VERSION 5.8 ;
BUSBITCHARS "[]" ;
DIVIDERCHAR "/" ;
UNITS
    DATABASE MICRONS 1000 ;
END UNITS

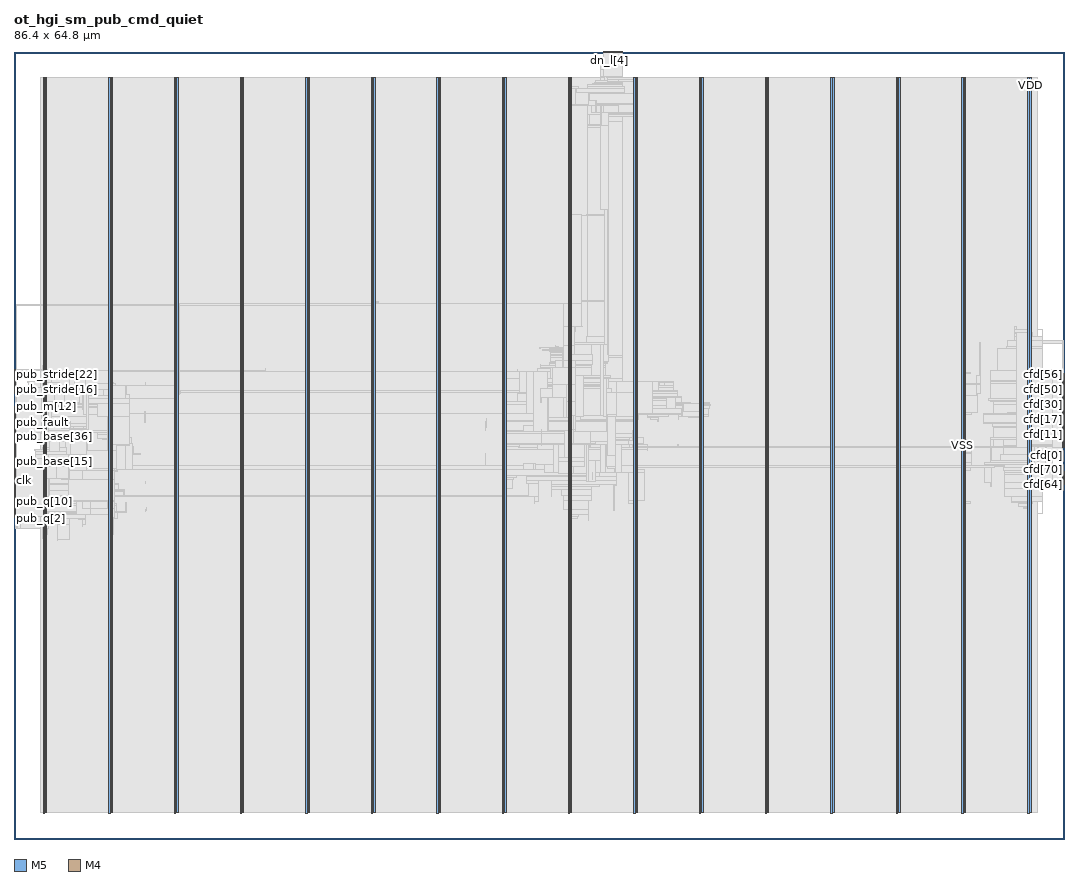
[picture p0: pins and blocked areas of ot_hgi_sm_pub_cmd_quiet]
MACRO ot_hgi_sm_pub_cmd_quiet
  FOREIGN ot_hgi_sm_pub_cmd_quiet 0 0 ;
  CLASS BLOCK ;
  SIZE 86.4 BY 64.8 ;
  PIN agg_r
    DIRECTION INPUT ;
    USE SIGNAL ;
    PORT
      LAYER M5 ;
        RECT  48.528 64.716 48.552 64.8 ;
    END
  END agg_r
  PIN cfd[0]
    DIRECTION OUTPUT ;
    USE SIGNAL ;
    PORT
      LAYER M4 ;
        RECT  86.316 32.208 86.4 32.232 ;
    END
  END cfd[0]
  PIN cfd[10]
    DIRECTION OUTPUT ;
    USE SIGNAL ;
    PORT
      LAYER M4 ;
        RECT  86.316 33.168 86.4 33.192 ;
    END
  END cfd[10]
  PIN cfd[11]
    DIRECTION OUTPUT ;
    USE SIGNAL ;
    PORT
      LAYER M4 ;
        RECT  86.316 33.264 86.4 33.288 ;
    END
  END cfd[11]
  PIN cfd[12]
    DIRECTION OUTPUT ;
    USE SIGNAL ;
    PORT
      LAYER M4 ;
        RECT  86.316 33.36 86.4 33.384 ;
    END
  END cfd[12]
  PIN cfd[13]
    DIRECTION OUTPUT ;
    USE SIGNAL ;
    PORT
      LAYER M4 ;
        RECT  86.316 33.456 86.4 33.48 ;
    END
  END cfd[13]
  PIN cfd[14]
    DIRECTION OUTPUT ;
    USE SIGNAL ;
    PORT
      LAYER M4 ;
        RECT  86.316 33.552 86.4 33.576 ;
    END
  END cfd[14]
  PIN cfd[15]
    DIRECTION OUTPUT ;
    USE SIGNAL ;
    PORT
      LAYER M4 ;
        RECT  86.316 33.648 86.4 33.672 ;
    END
  END cfd[15]
  PIN cfd[16]
    DIRECTION OUTPUT ;
    USE SIGNAL ;
    PORT
      LAYER M4 ;
        RECT  86.316 33.744 86.4 33.768 ;
    END
  END cfd[16]
  PIN cfd[17]
    DIRECTION OUTPUT ;
    USE SIGNAL ;
    PORT
      LAYER M4 ;
        RECT  86.316 33.84 86.4 33.864 ;
    END
  END cfd[17]
  PIN cfd[18]
    DIRECTION OUTPUT ;
    USE SIGNAL ;
    PORT
      LAYER M4 ;
        RECT  86.316 33.936 86.4 33.96 ;
    END
  END cfd[18]
  PIN cfd[19]
    DIRECTION OUTPUT ;
    USE SIGNAL ;
    PORT
      LAYER M4 ;
        RECT  86.316 34.032 86.4 34.056 ;
    END
  END cfd[19]
  PIN cfd[1]
    DIRECTION OUTPUT ;
    USE SIGNAL ;
    PORT
      LAYER M4 ;
        RECT  86.316 32.304 86.4 32.328 ;
    END
  END cfd[1]
  PIN cfd[20]
    DIRECTION OUTPUT ;
    USE SIGNAL ;
    PORT
      LAYER M4 ;
        RECT  86.316 34.128 86.4 34.152 ;
    END
  END cfd[20]
  PIN cfd[21]
    DIRECTION OUTPUT ;
    USE SIGNAL ;
    PORT
      LAYER M4 ;
        RECT  86.316 34.224 86.4 34.248 ;
    END
  END cfd[21]
  PIN cfd[22]
    DIRECTION OUTPUT ;
    USE SIGNAL ;
    PORT
      LAYER M4 ;
        RECT  86.316 34.32 86.4 34.344 ;
    END
  END cfd[22]
  PIN cfd[23]
    DIRECTION OUTPUT ;
    USE SIGNAL ;
    PORT
      LAYER M4 ;
        RECT  86.316 34.416 86.4 34.44 ;
    END
  END cfd[23]
  PIN cfd[24]
    DIRECTION OUTPUT ;
    USE SIGNAL ;
    PORT
      LAYER M4 ;
        RECT  86.316 34.512 86.4 34.536 ;
    END
  END cfd[24]
  PIN cfd[25]
    DIRECTION OUTPUT ;
    USE SIGNAL ;
    PORT
      LAYER M4 ;
        RECT  86.316 34.608 86.4 34.632 ;
    END
  END cfd[25]
  PIN cfd[26]
    DIRECTION OUTPUT ;
    USE SIGNAL ;
    PORT
      LAYER M4 ;
        RECT  86.316 34.704 86.4 34.728 ;
    END
  END cfd[26]
  PIN cfd[27]
    DIRECTION OUTPUT ;
    USE SIGNAL ;
    PORT
      LAYER M4 ;
        RECT  86.316 34.8 86.4 34.824 ;
    END
  END cfd[27]
  PIN cfd[28]
    DIRECTION OUTPUT ;
    USE SIGNAL ;
    PORT
      LAYER M4 ;
        RECT  86.316 34.896 86.4 34.92 ;
    END
  END cfd[28]
  PIN cfd[29]
    DIRECTION OUTPUT ;
    USE SIGNAL ;
    PORT
      LAYER M4 ;
        RECT  86.316 34.992 86.4 35.016 ;
    END
  END cfd[29]
  PIN cfd[2]
    DIRECTION OUTPUT ;
    USE SIGNAL ;
    PORT
      LAYER M4 ;
        RECT  86.316 32.4 86.4 32.424 ;
    END
  END cfd[2]
  PIN cfd[30]
    DIRECTION OUTPUT ;
    USE SIGNAL ;
    PORT
      LAYER M4 ;
        RECT  86.316 35.088 86.4 35.112 ;
    END
  END cfd[30]
  PIN cfd[31]
    DIRECTION OUTPUT ;
    USE SIGNAL ;
    PORT
      LAYER M4 ;
        RECT  86.316 35.184 86.4 35.208 ;
    END
  END cfd[31]
  PIN cfd[32]
    DIRECTION OUTPUT ;
    USE SIGNAL ;
    PORT
      LAYER M4 ;
        RECT  86.316 35.28 86.4 35.304 ;
    END
  END cfd[32]
  PIN cfd[33]
    DIRECTION OUTPUT ;
    USE SIGNAL ;
    PORT
      LAYER M4 ;
        RECT  86.316 35.376 86.4 35.4 ;
    END
  END cfd[33]
  PIN cfd[34]
    DIRECTION OUTPUT ;
    USE SIGNAL ;
    PORT
      LAYER M4 ;
        RECT  86.316 35.472 86.4 35.496 ;
    END
  END cfd[34]
  PIN cfd[35]
    DIRECTION OUTPUT ;
    USE SIGNAL ;
    PORT
      LAYER M4 ;
        RECT  86.316 35.568 86.4 35.592 ;
    END
  END cfd[35]
  PIN cfd[36]
    DIRECTION OUTPUT ;
    USE SIGNAL ;
    PORT
      LAYER M4 ;
        RECT  86.316 35.664 86.4 35.688 ;
    END
  END cfd[36]
  PIN cfd[37]
    DIRECTION OUTPUT ;
    USE SIGNAL ;
    PORT
      LAYER M4 ;
        RECT  86.316 35.76 86.4 35.784 ;
    END
  END cfd[37]
  PIN cfd[38]
    DIRECTION OUTPUT ;
    USE SIGNAL ;
    PORT
      LAYER M4 ;
        RECT  86.316 35.856 86.4 35.88 ;
    END
  END cfd[38]
  PIN cfd[39]
    DIRECTION OUTPUT ;
    USE SIGNAL ;
    PORT
      LAYER M4 ;
        RECT  86.316 35.952 86.4 35.976 ;
    END
  END cfd[39]
  PIN cfd[3]
    DIRECTION OUTPUT ;
    USE SIGNAL ;
    PORT
      LAYER M4 ;
        RECT  86.316 32.496 86.4 32.52 ;
    END
  END cfd[3]
  PIN cfd[40]
    DIRECTION OUTPUT ;
    USE SIGNAL ;
    PORT
      LAYER M4 ;
        RECT  86.316 36.048 86.4 36.072 ;
    END
  END cfd[40]
  PIN cfd[41]
    DIRECTION OUTPUT ;
    USE SIGNAL ;
    PORT
      LAYER M4 ;
        RECT  86.316 36.144 86.4 36.168 ;
    END
  END cfd[41]
  PIN cfd[42]
    DIRECTION OUTPUT ;
    USE SIGNAL ;
    PORT
      LAYER M4 ;
        RECT  86.316 36.24 86.4 36.264 ;
    END
  END cfd[42]
  PIN cfd[43]
    DIRECTION OUTPUT ;
    USE SIGNAL ;
    PORT
      LAYER M4 ;
        RECT  86.316 36.336 86.4 36.36 ;
    END
  END cfd[43]
  PIN cfd[44]
    DIRECTION OUTPUT ;
    USE SIGNAL ;
    PORT
      LAYER M4 ;
        RECT  86.316 36.432 86.4 36.456 ;
    END
  END cfd[44]
  PIN cfd[45]
    DIRECTION OUTPUT ;
    USE SIGNAL ;
    PORT
      LAYER M4 ;
        RECT  86.316 36.528 86.4 36.552 ;
    END
  END cfd[45]
  PIN cfd[46]
    DIRECTION OUTPUT ;
    USE SIGNAL ;
    PORT
      LAYER M4 ;
        RECT  86.316 36.624 86.4 36.648 ;
    END
  END cfd[46]
  PIN cfd[47]
    DIRECTION OUTPUT ;
    USE SIGNAL ;
    PORT
      LAYER M4 ;
        RECT  86.316 36.72 86.4 36.744 ;
    END
  END cfd[47]
  PIN cfd[48]
    DIRECTION OUTPUT ;
    USE SIGNAL ;
    PORT
      LAYER M4 ;
        RECT  86.316 36.816 86.4 36.84 ;
    END
  END cfd[48]
  PIN cfd[49]
    DIRECTION OUTPUT ;
    USE SIGNAL ;
    PORT
      LAYER M4 ;
        RECT  86.316 36.912 86.4 36.936 ;
    END
  END cfd[49]
  PIN cfd[4]
    DIRECTION OUTPUT ;
    USE SIGNAL ;
    PORT
      LAYER M4 ;
        RECT  86.316 32.592 86.4 32.616 ;
    END
  END cfd[4]
  PIN cfd[50]
    DIRECTION OUTPUT ;
    USE SIGNAL ;
    PORT
      LAYER M4 ;
        RECT  86.316 37.008 86.4 37.032 ;
    END
  END cfd[50]
  PIN cfd[51]
    DIRECTION OUTPUT ;
    USE SIGNAL ;
    PORT
      LAYER M4 ;
        RECT  86.316 37.104 86.4 37.128 ;
    END
  END cfd[51]
  PIN cfd[52]
    DIRECTION OUTPUT ;
    USE SIGNAL ;
    PORT
      LAYER M4 ;
        RECT  86.316 37.2 86.4 37.224 ;
    END
  END cfd[52]
  PIN cfd[53]
    DIRECTION OUTPUT ;
    USE SIGNAL ;
    PORT
      LAYER M4 ;
        RECT  86.316 37.296 86.4 37.32 ;
    END
  END cfd[53]
  PIN cfd[54]
    DIRECTION OUTPUT ;
    USE SIGNAL ;
    PORT
      LAYER M4 ;
        RECT  86.316 37.392 86.4 37.416 ;
    END
  END cfd[54]
  PIN cfd[55]
    DIRECTION OUTPUT ;
    USE SIGNAL ;
    PORT
      LAYER M4 ;
        RECT  86.316 37.488 86.4 37.512 ;
    END
  END cfd[55]
  PIN cfd[56]
    DIRECTION OUTPUT ;
    USE SIGNAL ;
    PORT
      LAYER M4 ;
        RECT  86.316 37.584 86.4 37.608 ;
    END
  END cfd[56]
  PIN cfd[57]
    DIRECTION OUTPUT ;
    USE SIGNAL ;
    PORT
      LAYER M4 ;
        RECT  86.316 37.68 86.4 37.704 ;
    END
  END cfd[57]
  PIN cfd[58]
    DIRECTION OUTPUT ;
    USE SIGNAL ;
    PORT
      LAYER M4 ;
        RECT  86.316 37.776 86.4 37.8 ;
    END
  END cfd[58]
  PIN cfd[59]
    DIRECTION OUTPUT ;
    USE SIGNAL ;
    PORT
      LAYER M4 ;
        RECT  86.316 37.872 86.4 37.896 ;
    END
  END cfd[59]
  PIN cfd[5]
    DIRECTION OUTPUT ;
    USE SIGNAL ;
    PORT
      LAYER M4 ;
        RECT  86.316 32.688 86.4 32.712 ;
    END
  END cfd[5]
  PIN cfd[60]
    DIRECTION OUTPUT ;
    USE SIGNAL ;
    PORT
      LAYER M4 ;
        RECT  86.316 37.968 86.4 37.992 ;
    END
  END cfd[60]
  PIN cfd[61]
    DIRECTION OUTPUT ;
    USE SIGNAL ;
    PORT
      LAYER M4 ;
        RECT  86.316 38.064 86.4 38.088 ;
    END
  END cfd[61]
  PIN cfd[62]
    DIRECTION OUTPUT ;
    USE SIGNAL ;
    PORT
      LAYER M4 ;
        RECT  86.316 38.16 86.4 38.184 ;
    END
  END cfd[62]
  PIN cfd[63]
    DIRECTION OUTPUT ;
    USE SIGNAL ;
    PORT
      LAYER M4 ;
        RECT  86.316 38.256 86.4 38.28 ;
    END
  END cfd[63]
  PIN cfd[64]
    DIRECTION OUTPUT ;
    USE SIGNAL ;
    PORT
      LAYER M4 ;
        RECT  86.316 29.136 86.4 29.16 ;
    END
  END cfd[64]
  PIN cfd[65]
    DIRECTION OUTPUT ;
    USE SIGNAL ;
    PORT
      LAYER M4 ;
        RECT  86.316 29.232 86.4 29.256 ;
    END
  END cfd[65]
  PIN cfd[66]
    DIRECTION OUTPUT ;
    USE SIGNAL ;
    PORT
      LAYER M4 ;
        RECT  86.316 29.328 86.4 29.352 ;
    END
  END cfd[66]
  PIN cfd[67]
    DIRECTION OUTPUT ;
    USE SIGNAL ;
    PORT
      LAYER M4 ;
        RECT  86.316 29.424 86.4 29.448 ;
    END
  END cfd[67]
  PIN cfd[68]
    DIRECTION OUTPUT ;
    USE SIGNAL ;
    PORT
      LAYER M4 ;
        RECT  86.316 29.52 86.4 29.544 ;
    END
  END cfd[68]
  PIN cfd[69]
    DIRECTION OUTPUT ;
    USE SIGNAL ;
    PORT
      LAYER M4 ;
        RECT  86.316 29.616 86.4 29.64 ;
    END
  END cfd[69]
  PIN cfd[6]
    DIRECTION OUTPUT ;
    USE SIGNAL ;
    PORT
      LAYER M4 ;
        RECT  86.316 32.784 86.4 32.808 ;
    END
  END cfd[6]
  PIN cfd[70]
    DIRECTION OUTPUT ;
    USE SIGNAL ;
    PORT
      LAYER M4 ;
        RECT  86.316 29.712 86.4 29.736 ;
    END
  END cfd[70]
  PIN cfd[71]
    DIRECTION OUTPUT ;
    USE SIGNAL ;
    PORT
      LAYER M4 ;
        RECT  86.316 29.808 86.4 29.832 ;
    END
  END cfd[71]
  PIN cfd[72]
    DIRECTION OUTPUT ;
    USE SIGNAL ;
    PORT
      LAYER M4 ;
        RECT  86.316 29.904 86.4 29.928 ;
    END
  END cfd[72]
  PIN cfd[73]
    DIRECTION OUTPUT ;
    USE SIGNAL ;
    PORT
      LAYER M4 ;
        RECT  86.316 30 86.4 30.024 ;
    END
  END cfd[73]
  PIN cfd[74]
    DIRECTION OUTPUT ;
    USE SIGNAL ;
    PORT
      LAYER M4 ;
        RECT  86.316 30.096 86.4 30.12 ;
    END
  END cfd[74]
  PIN cfd[7]
    DIRECTION OUTPUT ;
    USE SIGNAL ;
    PORT
      LAYER M4 ;
        RECT  86.316 32.88 86.4 32.904 ;
    END
  END cfd[7]
  PIN cfd[8]
    DIRECTION OUTPUT ;
    USE SIGNAL ;
    PORT
      LAYER M4 ;
        RECT  86.316 32.976 86.4 33 ;
    END
  END cfd[8]
  PIN cfd[9]
    DIRECTION OUTPUT ;
    USE SIGNAL ;
    PORT
      LAYER M4 ;
        RECT  86.316 33.072 86.4 33.096 ;
    END
  END cfd[9]
  PIN cgo
    DIRECTION OUTPUT ;
    USE SIGNAL ;
    PORT
      LAYER M4 ;
        RECT  86.316 30.192 86.4 30.216 ;
    END
  END cgo
  PIN clk
    DIRECTION INPUT ;
    USE SIGNAL ;
    PORT
      LAYER M4 ;
        RECT  0 29.52 0.084 29.544 ;
    END
  END clk
  PIN dn_l[0]
    DIRECTION INPUT ;
    USE SIGNAL ;
    PORT
      LAYER M5 ;
        RECT  48.624 64.716 48.648 64.8 ;
    END
  END dn_l[0]
  PIN dn_l[1]
    DIRECTION INPUT ;
    USE SIGNAL ;
    PORT
      LAYER M5 ;
        RECT  48.72 64.716 48.744 64.8 ;
    END
  END dn_l[1]
  PIN dn_l[2]
    DIRECTION INPUT ;
    USE SIGNAL ;
    PORT
      LAYER M5 ;
        RECT  48.816 64.716 48.84 64.8 ;
    END
  END dn_l[2]
  PIN dn_l[3]
    DIRECTION INPUT ;
    USE SIGNAL ;
    PORT
      LAYER M5 ;
        RECT  48.912 64.716 48.936 64.8 ;
    END
  END dn_l[3]
  PIN dn_l[4]
    DIRECTION INPUT ;
    USE SIGNAL ;
    PORT
      LAYER M5 ;
        RECT  49.008 64.716 49.032 64.8 ;
    END
  END dn_l[4]
  PIN dn_l[5]
    DIRECTION INPUT ;
    USE SIGNAL ;
    PORT
      LAYER M5 ;
        RECT  49.104 64.716 49.128 64.8 ;
    END
  END dn_l[5]
  PIN dn_l[6]
    DIRECTION INPUT ;
    USE SIGNAL ;
    PORT
      LAYER M5 ;
        RECT  49.2 64.716 49.224 64.8 ;
    END
  END dn_l[6]
  PIN dn_l[7]
    DIRECTION INPUT ;
    USE SIGNAL ;
    PORT
      LAYER M5 ;
        RECT  49.296 64.716 49.32 64.8 ;
    END
  END dn_l[7]
  PIN ft_l[0]
    DIRECTION INPUT ;
    USE SIGNAL ;
    PORT
      LAYER M5 ;
        RECT  49.392 64.716 49.416 64.8 ;
    END
  END ft_l[0]
  PIN ft_l[1]
    DIRECTION INPUT ;
    USE SIGNAL ;
    PORT
      LAYER M5 ;
        RECT  49.488 64.716 49.512 64.8 ;
    END
  END ft_l[1]
  PIN ft_l[2]
    DIRECTION INPUT ;
    USE SIGNAL ;
    PORT
      LAYER M5 ;
        RECT  49.584 64.716 49.608 64.8 ;
    END
  END ft_l[2]
  PIN ft_l[3]
    DIRECTION INPUT ;
    USE SIGNAL ;
    PORT
      LAYER M5 ;
        RECT  49.68 64.716 49.704 64.8 ;
    END
  END ft_l[3]
  PIN ft_l[4]
    DIRECTION INPUT ;
    USE SIGNAL ;
    PORT
      LAYER M5 ;
        RECT  49.776 64.716 49.8 64.8 ;
    END
  END ft_l[4]
  PIN ft_l[5]
    DIRECTION INPUT ;
    USE SIGNAL ;
    PORT
      LAYER M5 ;
        RECT  49.872 64.716 49.896 64.8 ;
    END
  END ft_l[5]
  PIN ft_l[6]
    DIRECTION INPUT ;
    USE SIGNAL ;
    PORT
      LAYER M5 ;
        RECT  49.968 64.716 49.992 64.8 ;
    END
  END ft_l[6]
  PIN ft_l[7]
    DIRECTION INPUT ;
    USE SIGNAL ;
    PORT
      LAYER M5 ;
        RECT  50.064 64.716 50.088 64.8 ;
    END
  END ft_l[7]
  PIN pub_base[0]
    DIRECTION INPUT ;
    USE SIGNAL ;
    PORT
      LAYER M4 ;
        RECT  0 29.616 0.084 29.64 ;
    END
  END pub_base[0]
  PIN pub_base[10]
    DIRECTION INPUT ;
    USE SIGNAL ;
    PORT
      LAYER M4 ;
        RECT  0 30.576 0.084 30.6 ;
    END
  END pub_base[10]
  PIN pub_base[11]
    DIRECTION INPUT ;
    USE SIGNAL ;
    PORT
      LAYER M4 ;
        RECT  0 30.672 0.084 30.696 ;
    END
  END pub_base[11]
  PIN pub_base[12]
    DIRECTION INPUT ;
    USE SIGNAL ;
    PORT
      LAYER M4 ;
        RECT  0 30.768 0.084 30.792 ;
    END
  END pub_base[12]
  PIN pub_base[13]
    DIRECTION INPUT ;
    USE SIGNAL ;
    PORT
      LAYER M4 ;
        RECT  0 30.864 0.084 30.888 ;
    END
  END pub_base[13]
  PIN pub_base[14]
    DIRECTION INPUT ;
    USE SIGNAL ;
    PORT
      LAYER M4 ;
        RECT  0 30.96 0.084 30.984 ;
    END
  END pub_base[14]
  PIN pub_base[15]
    DIRECTION INPUT ;
    USE SIGNAL ;
    PORT
      LAYER M4 ;
        RECT  0 31.056 0.084 31.08 ;
    END
  END pub_base[15]
  PIN pub_base[16]
    DIRECTION INPUT ;
    USE SIGNAL ;
    PORT
      LAYER M4 ;
        RECT  0 31.152 0.084 31.176 ;
    END
  END pub_base[16]
  PIN pub_base[17]
    DIRECTION INPUT ;
    USE SIGNAL ;
    PORT
      LAYER M4 ;
        RECT  0 31.248 0.084 31.272 ;
    END
  END pub_base[17]
  PIN pub_base[18]
    DIRECTION INPUT ;
    USE SIGNAL ;
    PORT
      LAYER M4 ;
        RECT  0 31.344 0.084 31.368 ;
    END
  END pub_base[18]
  PIN pub_base[19]
    DIRECTION INPUT ;
    USE SIGNAL ;
    PORT
      LAYER M4 ;
        RECT  0 31.44 0.084 31.464 ;
    END
  END pub_base[19]
  PIN pub_base[1]
    DIRECTION INPUT ;
    USE SIGNAL ;
    PORT
      LAYER M4 ;
        RECT  0 29.712 0.084 29.736 ;
    END
  END pub_base[1]
  PIN pub_base[20]
    DIRECTION INPUT ;
    USE SIGNAL ;
    PORT
      LAYER M4 ;
        RECT  0 31.536 0.084 31.56 ;
    END
  END pub_base[20]
  PIN pub_base[21]
    DIRECTION INPUT ;
    USE SIGNAL ;
    PORT
      LAYER M4 ;
        RECT  0 31.632 0.084 31.656 ;
    END
  END pub_base[21]
  PIN pub_base[22]
    DIRECTION INPUT ;
    USE SIGNAL ;
    PORT
      LAYER M4 ;
        RECT  0 31.728 0.084 31.752 ;
    END
  END pub_base[22]
  PIN pub_base[23]
    DIRECTION INPUT ;
    USE SIGNAL ;
    PORT
      LAYER M4 ;
        RECT  0 31.824 0.084 31.848 ;
    END
  END pub_base[23]
  PIN pub_base[24]
    DIRECTION INPUT ;
    USE SIGNAL ;
    PORT
      LAYER M4 ;
        RECT  0 31.92 0.084 31.944 ;
    END
  END pub_base[24]
  PIN pub_base[25]
    DIRECTION INPUT ;
    USE SIGNAL ;
    PORT
      LAYER M4 ;
        RECT  0 32.016 0.084 32.04 ;
    END
  END pub_base[25]
  PIN pub_base[26]
    DIRECTION INPUT ;
    USE SIGNAL ;
    PORT
      LAYER M4 ;
        RECT  0 32.112 0.084 32.136 ;
    END
  END pub_base[26]
  PIN pub_base[27]
    DIRECTION INPUT ;
    USE SIGNAL ;
    PORT
      LAYER M4 ;
        RECT  0 32.208 0.084 32.232 ;
    END
  END pub_base[27]
  PIN pub_base[28]
    DIRECTION INPUT ;
    USE SIGNAL ;
    PORT
      LAYER M4 ;
        RECT  0 32.304 0.084 32.328 ;
    END
  END pub_base[28]
  PIN pub_base[29]
    DIRECTION INPUT ;
    USE SIGNAL ;
    PORT
      LAYER M4 ;
        RECT  0 32.4 0.084 32.424 ;
    END
  END pub_base[29]
  PIN pub_base[2]
    DIRECTION INPUT ;
    USE SIGNAL ;
    PORT
      LAYER M4 ;
        RECT  0 29.808 0.084 29.832 ;
    END
  END pub_base[2]
  PIN pub_base[30]
    DIRECTION INPUT ;
    USE SIGNAL ;
    PORT
      LAYER M4 ;
        RECT  0 32.496 0.084 32.52 ;
    END
  END pub_base[30]
  PIN pub_base[31]
    DIRECTION INPUT ;
    USE SIGNAL ;
    PORT
      LAYER M4 ;
        RECT  0 32.592 0.084 32.616 ;
    END
  END pub_base[31]
  PIN pub_base[32]
    DIRECTION INPUT ;
    USE SIGNAL ;
    PORT
      LAYER M4 ;
        RECT  0 32.688 0.084 32.712 ;
    END
  END pub_base[32]
  PIN pub_base[33]
    DIRECTION INPUT ;
    USE SIGNAL ;
    PORT
      LAYER M4 ;
        RECT  0 32.784 0.084 32.808 ;
    END
  END pub_base[33]
  PIN pub_base[34]
    DIRECTION INPUT ;
    USE SIGNAL ;
    PORT
      LAYER M4 ;
        RECT  0 32.88 0.084 32.904 ;
    END
  END pub_base[34]
  PIN pub_base[35]
    DIRECTION INPUT ;
    USE SIGNAL ;
    PORT
      LAYER M4 ;
        RECT  0 32.976 0.084 33 ;
    END
  END pub_base[35]
  PIN pub_base[36]
    DIRECTION INPUT ;
    USE SIGNAL ;
    PORT
      LAYER M4 ;
        RECT  0 33.072 0.084 33.096 ;
    END
  END pub_base[36]
  PIN pub_base[37]
    DIRECTION INPUT ;
    USE SIGNAL ;
    PORT
      LAYER M4 ;
        RECT  0 33.168 0.084 33.192 ;
    END
  END pub_base[37]
  PIN pub_base[38]
    DIRECTION INPUT ;
    USE SIGNAL ;
    PORT
      LAYER M4 ;
        RECT  0 33.264 0.084 33.288 ;
    END
  END pub_base[38]
  PIN pub_base[39]
    DIRECTION INPUT ;
    USE SIGNAL ;
    PORT
      LAYER M4 ;
        RECT  0 33.36 0.084 33.384 ;
    END
  END pub_base[39]
  PIN pub_base[3]
    DIRECTION INPUT ;
    USE SIGNAL ;
    PORT
      LAYER M4 ;
        RECT  0 29.904 0.084 29.928 ;
    END
  END pub_base[3]
  PIN pub_base[4]
    DIRECTION INPUT ;
    USE SIGNAL ;
    PORT
      LAYER M4 ;
        RECT  0 30 0.084 30.024 ;
    END
  END pub_base[4]
  PIN pub_base[5]
    DIRECTION INPUT ;
    USE SIGNAL ;
    PORT
      LAYER M4 ;
        RECT  0 30.096 0.084 30.12 ;
    END
  END pub_base[5]
  PIN pub_base[6]
    DIRECTION INPUT ;
    USE SIGNAL ;
    PORT
      LAYER M4 ;
        RECT  0 30.192 0.084 30.216 ;
    END
  END pub_base[6]
  PIN pub_base[7]
    DIRECTION INPUT ;
    USE SIGNAL ;
    PORT
      LAYER M4 ;
        RECT  0 30.288 0.084 30.312 ;
    END
  END pub_base[7]
  PIN pub_base[8]
    DIRECTION INPUT ;
    USE SIGNAL ;
    PORT
      LAYER M4 ;
        RECT  0 30.384 0.084 30.408 ;
    END
  END pub_base[8]
  PIN pub_base[9]
    DIRECTION INPUT ;
    USE SIGNAL ;
    PORT
      LAYER M4 ;
        RECT  0 30.48 0.084 30.504 ;
    END
  END pub_base[9]
  PIN pub_bf16
    DIRECTION INPUT ;
    USE SIGNAL ;
    PORT
      LAYER M4 ;
        RECT  0 33.456 0.084 33.48 ;
    END
  END pub_bf16
  PIN pub_done
    DIRECTION OUTPUT ;
    USE SIGNAL ;
    PORT
      LAYER M4 ;
        RECT  0 33.552 0.084 33.576 ;
    END
  END pub_done
  PIN pub_fault
    DIRECTION OUTPUT ;
    USE SIGNAL ;
    PORT
      LAYER M4 ;
        RECT  0 33.648 0.084 33.672 ;
    END
  END pub_fault
  PIN pub_m[0]
    DIRECTION INPUT ;
    USE SIGNAL ;
    PORT
      LAYER M4 ;
        RECT  0 33.744 0.084 33.768 ;
    END
  END pub_m[0]
  PIN pub_m[10]
    DIRECTION INPUT ;
    USE SIGNAL ;
    PORT
      LAYER M4 ;
        RECT  0 34.704 0.084 34.728 ;
    END
  END pub_m[10]
  PIN pub_m[11]
    DIRECTION INPUT ;
    USE SIGNAL ;
    PORT
      LAYER M4 ;
        RECT  0 34.8 0.084 34.824 ;
    END
  END pub_m[11]
  PIN pub_m[12]
    DIRECTION INPUT ;
    USE SIGNAL ;
    PORT
      LAYER M4 ;
        RECT  0 34.896 0.084 34.92 ;
    END
  END pub_m[12]
  PIN pub_m[13]
    DIRECTION INPUT ;
    USE SIGNAL ;
    PORT
      LAYER M4 ;
        RECT  0 34.992 0.084 35.016 ;
    END
  END pub_m[13]
  PIN pub_m[14]
    DIRECTION INPUT ;
    USE SIGNAL ;
    PORT
      LAYER M4 ;
        RECT  0 35.088 0.084 35.112 ;
    END
  END pub_m[14]
  PIN pub_m[15]
    DIRECTION INPUT ;
    USE SIGNAL ;
    PORT
      LAYER M4 ;
        RECT  0 35.184 0.084 35.208 ;
    END
  END pub_m[15]
  PIN pub_m[16]
    DIRECTION INPUT ;
    USE SIGNAL ;
    PORT
      LAYER M4 ;
        RECT  0 35.28 0.084 35.304 ;
    END
  END pub_m[16]
  PIN pub_m[17]
    DIRECTION INPUT ;
    USE SIGNAL ;
    PORT
      LAYER M4 ;
        RECT  0 35.376 0.084 35.4 ;
    END
  END pub_m[17]
  PIN pub_m[18]
    DIRECTION INPUT ;
    USE SIGNAL ;
    PORT
      LAYER M4 ;
        RECT  0 35.472 0.084 35.496 ;
    END
  END pub_m[18]
  PIN pub_m[19]
    DIRECTION INPUT ;
    USE SIGNAL ;
    PORT
      LAYER M4 ;
        RECT  0 35.568 0.084 35.592 ;
    END
  END pub_m[19]
  PIN pub_m[1]
    DIRECTION INPUT ;
    USE SIGNAL ;
    PORT
      LAYER M4 ;
        RECT  0 33.84 0.084 33.864 ;
    END
  END pub_m[1]
  PIN pub_m[2]
    DIRECTION INPUT ;
    USE SIGNAL ;
    PORT
      LAYER M4 ;
        RECT  0 33.936 0.084 33.96 ;
    END
  END pub_m[2]
  PIN pub_m[3]
    DIRECTION INPUT ;
    USE SIGNAL ;
    PORT
      LAYER M4 ;
        RECT  0 34.032 0.084 34.056 ;
    END
  END pub_m[3]
  PIN pub_m[4]
    DIRECTION INPUT ;
    USE SIGNAL ;
    PORT
      LAYER M4 ;
        RECT  0 34.128 0.084 34.152 ;
    END
  END pub_m[4]
  PIN pub_m[5]
    DIRECTION INPUT ;
    USE SIGNAL ;
    PORT
      LAYER M4 ;
        RECT  0 34.224 0.084 34.248 ;
    END
  END pub_m[5]
  PIN pub_m[6]
    DIRECTION INPUT ;
    USE SIGNAL ;
    PORT
      LAYER M4 ;
        RECT  0 34.32 0.084 34.344 ;
    END
  END pub_m[6]
  PIN pub_m[7]
    DIRECTION INPUT ;
    USE SIGNAL ;
    PORT
      LAYER M4 ;
        RECT  0 34.416 0.084 34.44 ;
    END
  END pub_m[7]
  PIN pub_m[8]
    DIRECTION INPUT ;
    USE SIGNAL ;
    PORT
      LAYER M4 ;
        RECT  0 34.512 0.084 34.536 ;
    END
  END pub_m[8]
  PIN pub_m[9]
    DIRECTION INPUT ;
    USE SIGNAL ;
    PORT
      LAYER M4 ;
        RECT  0 34.608 0.084 34.632 ;
    END
  END pub_m[9]
  PIN pub_p[0]
    DIRECTION INPUT ;
    USE SIGNAL ;
    PORT
      LAYER M4 ;
        RECT  0 26.448 0.084 26.472 ;
    END
  END pub_p[0]
  PIN pub_p[1]
    DIRECTION INPUT ;
    USE SIGNAL ;
    PORT
      LAYER M4 ;
        RECT  0 26.544 0.084 26.568 ;
    END
  END pub_p[1]
  PIN pub_p[2]
    DIRECTION INPUT ;
    USE SIGNAL ;
    PORT
      LAYER M4 ;
        RECT  0 26.64 0.084 26.664 ;
    END
  END pub_p[2]
  PIN pub_p[3]
    DIRECTION INPUT ;
    USE SIGNAL ;
    PORT
      LAYER M4 ;
        RECT  0 26.736 0.084 26.76 ;
    END
  END pub_p[3]
  PIN pub_q[0]
    DIRECTION INPUT ;
    USE SIGNAL ;
    PORT
      LAYER M4 ;
        RECT  0 26.832 0.084 26.856 ;
    END
  END pub_q[0]
  PIN pub_q[10]
    DIRECTION INPUT ;
    USE SIGNAL ;
    PORT
      LAYER M4 ;
        RECT  0 27.792 0.084 27.816 ;
    END
  END pub_q[10]
  PIN pub_q[11]
    DIRECTION INPUT ;
    USE SIGNAL ;
    PORT
      LAYER M4 ;
        RECT  0 27.888 0.084 27.912 ;
    END
  END pub_q[11]
  PIN pub_q[12]
    DIRECTION INPUT ;
    USE SIGNAL ;
    PORT
      LAYER M4 ;
        RECT  0 27.984 0.084 28.008 ;
    END
  END pub_q[12]
  PIN pub_q[1]
    DIRECTION INPUT ;
    USE SIGNAL ;
    PORT
      LAYER M4 ;
        RECT  0 26.928 0.084 26.952 ;
    END
  END pub_q[1]
  PIN pub_q[2]
    DIRECTION INPUT ;
    USE SIGNAL ;
    PORT
      LAYER M4 ;
        RECT  0 27.024 0.084 27.048 ;
    END
  END pub_q[2]
  PIN pub_q[3]
    DIRECTION INPUT ;
    USE SIGNAL ;
    PORT
      LAYER M4 ;
        RECT  0 27.12 0.084 27.144 ;
    END
  END pub_q[3]
  PIN pub_q[4]
    DIRECTION INPUT ;
    USE SIGNAL ;
    PORT
      LAYER M4 ;
        RECT  0 27.216 0.084 27.24 ;
    END
  END pub_q[4]
  PIN pub_q[5]
    DIRECTION INPUT ;
    USE SIGNAL ;
    PORT
      LAYER M4 ;
        RECT  0 27.312 0.084 27.336 ;
    END
  END pub_q[5]
  PIN pub_q[6]
    DIRECTION INPUT ;
    USE SIGNAL ;
    PORT
      LAYER M4 ;
        RECT  0 27.408 0.084 27.432 ;
    END
  END pub_q[6]
  PIN pub_q[7]
    DIRECTION INPUT ;
    USE SIGNAL ;
    PORT
      LAYER M4 ;
        RECT  0 27.504 0.084 27.528 ;
    END
  END pub_q[7]
  PIN pub_q[8]
    DIRECTION INPUT ;
    USE SIGNAL ;
    PORT
      LAYER M4 ;
        RECT  0 27.6 0.084 27.624 ;
    END
  END pub_q[8]
  PIN pub_q[9]
    DIRECTION INPUT ;
    USE SIGNAL ;
    PORT
      LAYER M4 ;
        RECT  0 27.696 0.084 27.72 ;
    END
  END pub_q[9]
  PIN pub_rdy
    DIRECTION OUTPUT ;
    USE SIGNAL ;
    PORT
      LAYER M4 ;
        RECT  0 28.08 0.084 28.104 ;
    END
  END pub_rdy
  PIN pub_space[0]
    DIRECTION INPUT ;
    USE SIGNAL ;
    PORT
      LAYER M4 ;
        RECT  0 28.176 0.084 28.2 ;
    END
  END pub_space[0]
  PIN pub_space[1]
    DIRECTION INPUT ;
    USE SIGNAL ;
    PORT
      LAYER M4 ;
        RECT  0 28.272 0.084 28.296 ;
    END
  END pub_space[1]
  PIN pub_stride[0]
    DIRECTION INPUT ;
    USE SIGNAL ;
    PORT
      LAYER M4 ;
        RECT  0 28.368 0.084 28.392 ;
    END
  END pub_stride[0]
  PIN pub_stride[10]
    DIRECTION INPUT ;
    USE SIGNAL ;
    PORT
      LAYER M4 ;
        RECT  0 29.328 0.084 29.352 ;
    END
  END pub_stride[10]
  PIN pub_stride[11]
    DIRECTION INPUT ;
    USE SIGNAL ;
    PORT
      LAYER M4 ;
        RECT  0 29.424 0.084 29.448 ;
    END
  END pub_stride[11]
  PIN pub_stride[12]
    DIRECTION INPUT ;
    USE SIGNAL ;
    PORT
      LAYER M4 ;
        RECT  0 36.624 0.084 36.648 ;
    END
  END pub_stride[12]
  PIN pub_stride[13]
    DIRECTION INPUT ;
    USE SIGNAL ;
    PORT
      LAYER M4 ;
        RECT  0 36.72 0.084 36.744 ;
    END
  END pub_stride[13]
  PIN pub_stride[14]
    DIRECTION INPUT ;
    USE SIGNAL ;
    PORT
      LAYER M4 ;
        RECT  0 36.816 0.084 36.84 ;
    END
  END pub_stride[14]
  PIN pub_stride[15]
    DIRECTION INPUT ;
    USE SIGNAL ;
    PORT
      LAYER M4 ;
        RECT  0 36.912 0.084 36.936 ;
    END
  END pub_stride[15]
  PIN pub_stride[16]
    DIRECTION INPUT ;
    USE SIGNAL ;
    PORT
      LAYER M4 ;
        RECT  0 37.008 0.084 37.032 ;
    END
  END pub_stride[16]
  PIN pub_stride[17]
    DIRECTION INPUT ;
    USE SIGNAL ;
    PORT
      LAYER M4 ;
        RECT  0 37.104 0.084 37.128 ;
    END
  END pub_stride[17]
  PIN pub_stride[18]
    DIRECTION INPUT ;
    USE SIGNAL ;
    PORT
      LAYER M4 ;
        RECT  0 37.2 0.084 37.224 ;
    END
  END pub_stride[18]
  PIN pub_stride[19]
    DIRECTION INPUT ;
    USE SIGNAL ;
    PORT
      LAYER M4 ;
        RECT  0 37.296 0.084 37.32 ;
    END
  END pub_stride[19]
  PIN pub_stride[1]
    DIRECTION INPUT ;
    USE SIGNAL ;
    PORT
      LAYER M4 ;
        RECT  0 28.464 0.084 28.488 ;
    END
  END pub_stride[1]
  PIN pub_stride[20]
    DIRECTION INPUT ;
    USE SIGNAL ;
    PORT
      LAYER M4 ;
        RECT  0 37.392 0.084 37.416 ;
    END
  END pub_stride[20]
  PIN pub_stride[21]
    DIRECTION INPUT ;
    USE SIGNAL ;
    PORT
      LAYER M4 ;
        RECT  0 37.488 0.084 37.512 ;
    END
  END pub_stride[21]
  PIN pub_stride[22]
    DIRECTION INPUT ;
    USE SIGNAL ;
    PORT
      LAYER M4 ;
        RECT  0 37.584 0.084 37.608 ;
    END
  END pub_stride[22]
  PIN pub_stride[23]
    DIRECTION INPUT ;
    USE SIGNAL ;
    PORT
      LAYER M4 ;
        RECT  0 37.68 0.084 37.704 ;
    END
  END pub_stride[23]
  PIN pub_stride[24]
    DIRECTION INPUT ;
    USE SIGNAL ;
    PORT
      LAYER M4 ;
        RECT  0 37.776 0.084 37.8 ;
    END
  END pub_stride[24]
  PIN pub_stride[25]
    DIRECTION INPUT ;
    USE SIGNAL ;
    PORT
      LAYER M4 ;
        RECT  0 37.872 0.084 37.896 ;
    END
  END pub_stride[25]
  PIN pub_stride[26]
    DIRECTION INPUT ;
    USE SIGNAL ;
    PORT
      LAYER M4 ;
        RECT  0 37.968 0.084 37.992 ;
    END
  END pub_stride[26]
  PIN pub_stride[27]
    DIRECTION INPUT ;
    USE SIGNAL ;
    PORT
      LAYER M4 ;
        RECT  0 38.064 0.084 38.088 ;
    END
  END pub_stride[27]
  PIN pub_stride[28]
    DIRECTION INPUT ;
    USE SIGNAL ;
    PORT
      LAYER M4 ;
        RECT  0 38.16 0.084 38.184 ;
    END
  END pub_stride[28]
  PIN pub_stride[29]
    DIRECTION INPUT ;
    USE SIGNAL ;
    PORT
      LAYER M4 ;
        RECT  0 38.256 0.084 38.28 ;
    END
  END pub_stride[29]
  PIN pub_stride[2]
    DIRECTION INPUT ;
    USE SIGNAL ;
    PORT
      LAYER M4 ;
        RECT  0 28.56 0.084 28.584 ;
    END
  END pub_stride[2]
  PIN pub_stride[30]
    DIRECTION INPUT ;
    USE SIGNAL ;
    PORT
      LAYER M4 ;
        RECT  0 38.352 0.084 38.376 ;
    END
  END pub_stride[30]
  PIN pub_stride[31]
    DIRECTION INPUT ;
    USE SIGNAL ;
    PORT
      LAYER M4 ;
        RECT  0 38.448 0.084 38.472 ;
    END
  END pub_stride[31]
  PIN pub_stride[3]
    DIRECTION INPUT ;
    USE SIGNAL ;
    PORT
      LAYER M4 ;
        RECT  0 28.656 0.084 28.68 ;
    END
  END pub_stride[3]
  PIN pub_stride[4]
    DIRECTION INPUT ;
    USE SIGNAL ;
    PORT
      LAYER M4 ;
        RECT  0 28.752 0.084 28.776 ;
    END
  END pub_stride[4]
  PIN pub_stride[5]
    DIRECTION INPUT ;
    USE SIGNAL ;
    PORT
      LAYER M4 ;
        RECT  0 28.848 0.084 28.872 ;
    END
  END pub_stride[5]
  PIN pub_stride[6]
    DIRECTION INPUT ;
    USE SIGNAL ;
    PORT
      LAYER M4 ;
        RECT  0 28.944 0.084 28.968 ;
    END
  END pub_stride[6]
  PIN pub_stride[7]
    DIRECTION INPUT ;
    USE SIGNAL ;
    PORT
      LAYER M4 ;
        RECT  0 29.04 0.084 29.064 ;
    END
  END pub_stride[7]
  PIN pub_stride[8]
    DIRECTION INPUT ;
    USE SIGNAL ;
    PORT
      LAYER M4 ;
        RECT  0 29.136 0.084 29.16 ;
    END
  END pub_stride[8]
  PIN pub_stride[9]
    DIRECTION INPUT ;
    USE SIGNAL ;
    PORT
      LAYER M4 ;
        RECT  0 29.232 0.084 29.256 ;
    END
  END pub_stride[9]
  PIN pub_v
    DIRECTION INPUT ;
    USE SIGNAL ;
    PORT
      LAYER M4 ;
        RECT  0 38.544 0.084 38.568 ;
    END
  END pub_v
  PIN rn
    DIRECTION INPUT ;
    USE SIGNAL ;
    PORT
      LAYER M4 ;
        RECT  0 38.64 0.084 38.664 ;
    END
  END rn
  PIN VDD
    DIRECTION INOUT ;
    USE POWER ;
    PORT
      LAYER M5 ;
        RECT  83.592 2.151 83.712 62.649 ;
        RECT  78.192 2.151 78.312 62.649 ;
        RECT  72.792 2.151 72.912 62.649 ;
        RECT  67.392 2.151 67.512 62.649 ;
        RECT  61.992 2.151 62.112 62.649 ;
        RECT  56.592 2.151 56.712 62.649 ;
        RECT  51.192 2.151 51.312 62.649 ;
        RECT  45.792 2.151 45.912 62.649 ;
        RECT  40.392 2.151 40.512 62.649 ;
        RECT  34.992 2.151 35.112 62.649 ;
        RECT  29.592 2.151 29.712 62.649 ;
        RECT  24.192 2.151 24.312 62.649 ;
        RECT  18.792 2.151 18.912 62.649 ;
        RECT  13.392 2.151 13.512 62.649 ;
        RECT  7.992 2.151 8.112 62.649 ;
        RECT  2.592 2.151 2.712 62.649 ;
    END
  END VDD
  PIN VSS
    DIRECTION INOUT ;
    USE GROUND ;
    PORT
      LAYER M5 ;
        RECT  83.4 2.137 83.52 62.663 ;
        RECT  78 2.137 78.12 62.663 ;
        RECT  72.6 2.137 72.72 62.663 ;
        RECT  67.2 2.137 67.32 62.663 ;
        RECT  61.8 2.137 61.92 62.663 ;
        RECT  56.4 2.137 56.52 62.663 ;
        RECT  51 2.137 51.12 62.663 ;
        RECT  45.6 2.137 45.72 62.663 ;
        RECT  40.2 2.137 40.32 62.663 ;
        RECT  34.8 2.137 34.92 62.663 ;
        RECT  29.4 2.137 29.52 62.663 ;
        RECT  24 2.137 24.12 62.663 ;
        RECT  18.6 2.137 18.72 62.663 ;
        RECT  13.2 2.137 13.32 62.663 ;
        RECT  7.8 2.137 7.92 62.663 ;
        RECT  2.4 2.137 2.52 62.663 ;
    END
  END VSS
  # OT_OBS_CLOSED layer=M5 d_um=1.536 added=32
  OBS
    LAYER RVTN ;
     RECT  2.16 2.16 84.24 2.295 ;
     RECT  2.16 2.565 84.24 2.835 ;
     RECT  2.16 3.105 84.24 3.375 ;
     RECT  2.16 3.645 84.24 3.915 ;
     RECT  2.16 4.185 84.24 4.455 ;
     RECT  2.16 4.725 84.24 4.995 ;
     RECT  2.16 5.265 84.24 5.535 ;
     RECT  2.16 5.805 84.24 6.075 ;
     RECT  2.16 6.345 84.24 6.615 ;
     RECT  2.16 6.885 84.24 7.155 ;
     RECT  2.16 7.425 84.24 7.695 ;
     RECT  2.16 7.965 84.24 8.235 ;
     RECT  2.16 8.505 84.24 8.775 ;
     RECT  2.16 9.045 84.24 9.315 ;
     RECT  2.16 9.585 84.24 9.855 ;
     RECT  2.16 10.125 84.24 10.395 ;
     RECT  2.16 10.665 84.24 10.935 ;
     RECT  2.16 11.205 84.24 11.475 ;
     RECT  2.16 11.745 84.24 12.015 ;
     RECT  2.16 12.285 84.24 12.555 ;
     RECT  2.16 12.825 84.24 13.095 ;
     RECT  2.16 13.365 84.24 13.635 ;
     RECT  2.16 13.905 84.24 14.175 ;
     RECT  2.16 14.445 84.24 14.715 ;
     RECT  2.16 14.985 84.24 15.255 ;
     RECT  2.16 15.525 84.24 15.795 ;
     RECT  2.16 16.065 84.24 16.335 ;
     RECT  2.16 16.605 84.24 16.875 ;
     RECT  2.16 17.145 84.24 17.415 ;
     RECT  2.16 17.685 84.24 17.955 ;
     RECT  2.16 18.225 84.24 18.495 ;
     RECT  2.16 18.765 84.24 19.035 ;
     RECT  2.16 19.305 84.24 19.575 ;
     RECT  2.16 19.845 84.24 20.115 ;
     RECT  2.16 20.385 84.24 20.655 ;
     RECT  2.16 20.925 84.24 21.195 ;
     RECT  2.16 21.465 84.24 21.735 ;
     RECT  2.16 22.005 84.24 22.275 ;
     RECT  2.16 22.545 84.24 22.815 ;
     RECT  2.16 23.085 84.24 23.355 ;
     RECT  2.16 23.625 84.24 23.895 ;
     RECT  2.16 24.165 84.24 24.435 ;
     RECT  2.16 24.705 84.24 24.975 ;
     RECT  2.16 25.245 84.24 25.515 ;
     RECT  2.16 25.785 84.24 26.055 ;
     RECT  2.16 26.325 84.24 26.595 ;
     RECT  2.16 26.865 84.24 27.135 ;
     RECT  2.16 27.405 84.24 27.675 ;
     RECT  2.16 27.945 84.24 28.215 ;
     RECT  2.16 28.485 84.24 28.755 ;
     RECT  2.16 29.025 84.24 29.295 ;
     RECT  2.16 29.565 84.24 29.835 ;
     RECT  2.16 30.105 84.24 30.375 ;
     RECT  2.16 30.645 84.24 30.915 ;
     RECT  2.16 31.185 84.24 31.455 ;
     RECT  2.16 31.725 84.24 31.995 ;
     RECT  2.16 32.265 84.24 32.535 ;
     RECT  2.16 32.805 84.24 33.075 ;
     RECT  2.16 33.345 84.24 33.615 ;
     RECT  2.16 33.885 84.24 34.155 ;
     RECT  2.16 34.425 84.24 34.695 ;
     RECT  2.16 34.965 84.24 35.235 ;
     RECT  2.16 35.505 84.24 35.775 ;
     RECT  2.16 36.045 84.24 36.315 ;
     RECT  2.16 36.585 84.24 36.855 ;
     RECT  2.16 37.125 84.24 37.395 ;
     RECT  2.16 37.665 84.24 37.935 ;
     RECT  2.16 38.205 84.24 38.475 ;
     RECT  2.16 38.745 84.24 39.015 ;
     RECT  2.16 39.285 84.24 39.555 ;
     RECT  2.16 39.825 84.24 40.095 ;
     RECT  2.16 40.365 84.24 40.635 ;
     RECT  2.16 40.905 84.24 41.175 ;
     RECT  2.16 41.445 84.24 41.715 ;
     RECT  2.16 41.985 84.24 42.255 ;
     RECT  2.16 42.525 84.24 42.795 ;
     RECT  2.16 43.065 84.24 43.335 ;
     RECT  2.16 43.605 84.24 43.875 ;
     RECT  2.16 44.145 84.24 44.415 ;
     RECT  2.16 44.685 84.24 44.955 ;
     RECT  2.16 45.225 84.24 45.495 ;
     RECT  2.16 45.765 84.24 46.035 ;
     RECT  2.16 46.305 84.24 46.575 ;
     RECT  2.16 46.845 84.24 47.115 ;
     RECT  2.16 47.385 84.24 47.655 ;
     RECT  2.16 47.925 84.24 48.195 ;
     RECT  2.16 48.465 84.24 48.735 ;
     RECT  2.16 49.005 84.24 49.275 ;
     RECT  2.16 49.545 84.24 49.815 ;
     RECT  2.16 50.085 84.24 50.355 ;
     RECT  2.16 50.625 84.24 50.895 ;
     RECT  2.16 51.165 84.24 51.435 ;
     RECT  2.16 51.705 84.24 51.975 ;
     RECT  2.16 52.245 84.24 52.515 ;
     RECT  2.16 52.785 84.24 53.055 ;
     RECT  2.16 53.325 84.24 53.595 ;
     RECT  2.16 53.865 84.24 54.135 ;
     RECT  2.16 54.405 84.24 54.675 ;
     RECT  2.16 54.945 84.24 55.215 ;
     RECT  2.16 55.485 84.24 55.755 ;
     RECT  2.16 56.025 84.24 56.295 ;
     RECT  2.16 56.565 84.24 56.835 ;
     RECT  2.16 57.105 84.24 57.375 ;
     RECT  2.16 57.645 84.24 57.915 ;
     RECT  2.16 58.185 84.24 58.455 ;
     RECT  2.16 58.725 84.24 58.995 ;
     RECT  2.16 59.265 84.24 59.535 ;
     RECT  2.16 59.805 84.24 60.075 ;
     RECT  2.16 60.345 84.24 60.615 ;
     RECT  2.16 60.885 84.24 61.155 ;
     RECT  2.16 61.425 84.24 61.695 ;
     RECT  2.16 61.965 84.24 62.235 ;
     RECT  2.16 62.505 84.24 62.64 ;
    LAYER RVTP ;
     RECT  2.16 2.295 84.24 2.565 ;
     RECT  2.16 2.835 84.24 3.105 ;
     RECT  2.16 3.375 84.24 3.645 ;
     RECT  2.16 3.915 84.24 4.185 ;
     RECT  2.16 4.455 84.24 4.725 ;
     RECT  2.16 4.995 84.24 5.265 ;
     RECT  2.16 5.535 84.24 5.805 ;
     RECT  2.16 6.075 84.24 6.345 ;
     RECT  2.16 6.615 84.24 6.885 ;
     RECT  2.16 7.155 84.24 7.425 ;
     RECT  2.16 7.695 84.24 7.965 ;
     RECT  2.16 8.235 84.24 8.505 ;
     RECT  2.16 8.775 84.24 9.045 ;
     RECT  2.16 9.315 84.24 9.585 ;
     RECT  2.16 9.855 84.24 10.125 ;
     RECT  2.16 10.395 84.24 10.665 ;
     RECT  2.16 10.935 84.24 11.205 ;
     RECT  2.16 11.475 84.24 11.745 ;
     RECT  2.16 12.015 84.24 12.285 ;
     RECT  2.16 12.555 84.24 12.825 ;
     RECT  2.16 13.095 84.24 13.365 ;
     RECT  2.16 13.635 84.24 13.905 ;
     RECT  2.16 14.175 84.24 14.445 ;
     RECT  2.16 14.715 84.24 14.985 ;
     RECT  2.16 15.255 84.24 15.525 ;
     RECT  2.16 15.795 84.24 16.065 ;
     RECT  2.16 16.335 84.24 16.605 ;
     RECT  2.16 16.875 84.24 17.145 ;
     RECT  2.16 17.415 84.24 17.685 ;
     RECT  2.16 17.955 84.24 18.225 ;
     RECT  2.16 18.495 84.24 18.765 ;
     RECT  2.16 19.035 84.24 19.305 ;
     RECT  2.16 19.575 84.24 19.845 ;
     RECT  2.16 20.115 84.24 20.385 ;
     RECT  2.16 20.655 84.24 20.925 ;
     RECT  2.16 21.195 84.24 21.465 ;
     RECT  2.16 21.735 84.24 22.005 ;
     RECT  2.16 22.275 84.24 22.545 ;
     RECT  2.16 22.815 84.24 23.085 ;
     RECT  2.16 23.355 84.24 23.625 ;
     RECT  2.16 23.895 84.24 24.165 ;
     RECT  2.16 24.435 84.24 24.705 ;
     RECT  2.16 24.975 84.24 25.245 ;
     RECT  2.16 25.515 84.24 25.785 ;
     RECT  2.16 26.055 84.24 26.325 ;
     RECT  2.16 26.595 84.24 26.865 ;
     RECT  2.16 27.135 84.24 27.405 ;
     RECT  2.16 27.675 84.24 27.945 ;
     RECT  2.16 28.215 84.24 28.485 ;
     RECT  2.16 28.755 84.24 29.025 ;
     RECT  2.16 29.295 84.24 29.565 ;
     RECT  2.16 29.835 84.24 30.105 ;
     RECT  2.16 30.375 84.24 30.645 ;
     RECT  2.16 30.915 84.24 31.185 ;
     RECT  2.16 31.455 84.24 31.725 ;
     RECT  2.16 31.995 84.24 32.265 ;
     RECT  2.16 32.535 84.24 32.805 ;
     RECT  2.16 33.075 84.24 33.345 ;
     RECT  2.16 33.615 84.24 33.885 ;
     RECT  2.16 34.155 84.24 34.425 ;
     RECT  2.16 34.695 84.24 34.965 ;
     RECT  2.16 35.235 84.24 35.505 ;
     RECT  2.16 35.775 84.24 36.045 ;
     RECT  2.16 36.315 84.24 36.585 ;
     RECT  2.16 36.855 84.24 37.125 ;
     RECT  2.16 37.395 84.24 37.665 ;
     RECT  2.16 37.935 84.24 38.205 ;
     RECT  2.16 38.475 84.24 38.745 ;
     RECT  2.16 39.015 84.24 39.285 ;
     RECT  2.16 39.555 84.24 39.825 ;
     RECT  2.16 40.095 84.24 40.365 ;
     RECT  2.16 40.635 84.24 40.905 ;
     RECT  2.16 41.175 84.24 41.445 ;
     RECT  2.16 41.715 84.24 41.985 ;
     RECT  2.16 42.255 84.24 42.525 ;
     RECT  2.16 42.795 84.24 43.065 ;
     RECT  2.16 43.335 84.24 43.605 ;
     RECT  2.16 43.875 84.24 44.145 ;
     RECT  2.16 44.415 84.24 44.685 ;
     RECT  2.16 44.955 84.24 45.225 ;
     RECT  2.16 45.495 84.24 45.765 ;
     RECT  2.16 46.035 84.24 46.305 ;
     RECT  2.16 46.575 84.24 46.845 ;
     RECT  2.16 47.115 84.24 47.385 ;
     RECT  2.16 47.655 84.24 47.925 ;
     RECT  2.16 48.195 84.24 48.465 ;
     RECT  2.16 48.735 84.24 49.005 ;
     RECT  2.16 49.275 84.24 49.545 ;
     RECT  2.16 49.815 84.24 50.085 ;
     RECT  2.16 50.355 84.24 50.625 ;
     RECT  2.16 50.895 84.24 51.165 ;
     RECT  2.16 51.435 84.24 51.705 ;
     RECT  2.16 51.975 84.24 52.245 ;
     RECT  2.16 52.515 84.24 52.785 ;
     RECT  2.16 53.055 84.24 53.325 ;
     RECT  2.16 53.595 84.24 53.865 ;
     RECT  2.16 54.135 84.24 54.405 ;
     RECT  2.16 54.675 84.24 54.945 ;
     RECT  2.16 55.215 84.24 55.485 ;
     RECT  2.16 55.755 84.24 56.025 ;
     RECT  2.16 56.295 84.24 56.565 ;
     RECT  2.16 56.835 84.24 57.105 ;
     RECT  2.16 57.375 84.24 57.645 ;
     RECT  2.16 57.915 84.24 58.185 ;
     RECT  2.16 58.455 84.24 58.725 ;
     RECT  2.16 58.995 84.24 59.265 ;
     RECT  2.16 59.535 84.24 59.805 ;
     RECT  2.16 60.075 84.24 60.345 ;
     RECT  2.16 60.615 84.24 60.885 ;
     RECT  2.16 61.155 84.24 61.425 ;
     RECT  2.16 61.695 84.24 61.965 ;
     RECT  2.16 62.235 84.24 62.505 ;
    LAYER M1 ;
     RECT  2.16 2.151 84.24 62.649 ;
    LAYER M2 ;
     RECT  0.103 32.85 0.139 32.868 ;
     RECT  0.103 25.56 0.175 25.578 ;
     RECT  0.139 26.37 0.175 26.388 ;
     RECT  0.103 29.61 0.175 29.628 ;
     RECT  0.103 27.882 0.211 27.9 ;
     RECT  0.175 25.56 0.247 26.388 ;
     RECT  0.103 34.821 0.347 34.839 ;
     RECT  0.211 27.684 0.463 27.9 ;
     RECT  0.247 25.56 0.499 26.658 ;
     RECT  0.463 27.684 0.499 28.206 ;
     RECT  0.499 25.56 0.535 28.206 ;
     RECT  0.175 29.34 0.535 29.628 ;
     RECT  0.139 32.85 0.535 33.066 ;
     RECT  1.147 37.602 1.183 37.62 ;
     RECT  0.535 25.56 2.16 29.628 ;
     RECT  1.723 32.004 2.16 32.022 ;
     RECT  0.535 32.85 2.16 33.444 ;
     RECT  1.183 37.17 2.16 37.62 ;
     RECT  2.16 2.151 84.24 62.649 ;
     RECT  84.24 28.458 84.335 38.664 ;
     RECT  84.335 28.458 84.371 28.476 ;
     RECT  84.24 26.766 84.659 26.784 ;
     RECT  84.24 41.886 84.659 41.904 ;
     RECT  84.335 29.376 84.911 38.664 ;
     RECT  84.911 30.114 85.451 38.664 ;
     RECT  85.451 30.276 85.487 35.964 ;
     RECT  85.451 36.756 85.487 38.124 ;
     RECT  85.487 31.734 85.523 33.714 ;
     RECT  85.487 34.506 85.523 34.758 ;
     RECT  85.487 37.026 85.523 38.034 ;
     RECT  85.523 34.74 85.559 34.758 ;
     RECT  85.523 31.734 86.279 31.914 ;
     RECT  85.523 38.016 86.287 38.034 ;
     RECT  86.279 31.734 86.315 31.752 ;
     RECT  85.523 33.048 86.315 33.066 ;
     RECT  85.487 35.784 86.315 35.802 ;
     RECT  85.523 37.026 86.315 37.044 ;
     RECT  86.287 38.016 86.315 38.196 ;
     RECT  84.24 40.806 86.315 41.004 ;
     RECT  86.315 38.178 86.387 38.196 ;
     RECT  86.315 40.986 86.387 41.004 ;
    LAYER M3 ;
     RECT  2.415 2.143 2.505 2.413 ;
     RECT  7.815 2.143 7.905 2.413 ;
     RECT  13.215 2.143 13.305 2.413 ;
     RECT  18.615 2.143 18.705 2.413 ;
     RECT  24.015 2.143 24.105 2.413 ;
     RECT  29.415 2.143 29.505 2.413 ;
     RECT  34.815 2.143 34.905 2.413 ;
     RECT  40.215 2.143 40.305 2.413 ;
     RECT  45.615 2.143 45.705 2.413 ;
     RECT  51.015 2.143 51.105 2.413 ;
     RECT  56.415 2.143 56.505 2.413 ;
     RECT  61.815 2.143 61.905 2.413 ;
     RECT  67.215 2.143 67.305 2.413 ;
     RECT  72.615 2.143 72.705 2.413 ;
     RECT  78.015 2.143 78.105 2.413 ;
     RECT  83.415 2.143 83.505 2.413 ;
     RECT  3.6 24.601 3.618 24.637 ;
     RECT  2.415 2.413 2.697 24.745 ;
     RECT  2.34 24.745 2.697 25.015 ;
     RECT  2.304 25.015 2.697 25.051 ;
     RECT  7.815 2.413 8.097 25.051 ;
     RECT  2.304 25.051 2.754 25.519 ;
     RECT  3.6 24.637 4.59 25.861 ;
     RECT  5.652 25.717 5.67 25.861 ;
     RECT  0.108 25.555 0.126 26.059 ;
     RECT  5.652 25.861 5.886 26.329 ;
     RECT  3.564 25.861 4.59 26.365 ;
     RECT  5.328 26.329 5.886 26.365 ;
     RECT  7.815 25.051 8.154 26.365 ;
     RECT  2.304 25.519 2.826 26.401 ;
     RECT  3.564 26.365 5.886 26.401 ;
     RECT  45.615 2.413 45.897 26.401 ;
     RECT  0.108 26.059 0.234 26.477 ;
     RECT  45.615 26.401 46.386 26.563 ;
     RECT  0.144 26.477 0.234 26.635 ;
     RECT  45.615 26.563 46.458 26.671 ;
     RECT  47.232 26.221 47.25 26.671 ;
     RECT  2.304 26.401 5.886 26.761 ;
     RECT  7.815 26.365 8.478 26.833 ;
     RECT  2.304 26.761 6.606 26.869 ;
     RECT  83.415 2.413 83.697 26.905 ;
     RECT  7.815 26.833 9.234 26.933 ;
     RECT  2.304 26.869 6.714 26.941 ;
     RECT  7.815 26.933 8.406 26.941 ;
     RECT  0.144 26.635 0.27 26.957 ;
     RECT  0.18 26.957 0.27 27.053 ;
     RECT  0.216 27.053 0.27 27.067 ;
     RECT  10.8 26.941 10.818 27.067 ;
     RECT  45.615 26.671 47.25 27.103 ;
     RECT  10.8 27.067 10.926 27.131 ;
     RECT  83.376 26.905 83.697 27.211 ;
     RECT  10.908 27.131 10.926 27.239 ;
     RECT  83.088 27.211 83.697 27.301 ;
     RECT  9.144 26.933 9.234 27.329 ;
     RECT  83.088 27.301 83.754 27.337 ;
     RECT  2.304 26.941 8.406 27.445 ;
     RECT  51.015 2.413 51.297 27.571 ;
     RECT  78.015 2.413 78.297 27.571 ;
     RECT  82.656 27.337 83.754 27.571 ;
     RECT  2.268 27.445 8.406 27.599 ;
     RECT  9.216 27.329 9.234 27.671 ;
     RECT  82.656 27.571 83.79 27.679 ;
     RECT  82.548 27.679 83.79 27.715 ;
     RECT  42.804 27.607 42.822 27.751 ;
     RECT  82.08 27.715 83.79 27.751 ;
     RECT  84.636 26.761 84.654 27.751 ;
     RECT  6.588 27.599 8.262 27.779 ;
     RECT  78.015 27.571 78.678 27.779 ;
     RECT  6.624 27.779 8.262 27.821 ;
     RECT  50.544 27.571 51.297 27.841 ;
     RECT  0.216 27.067 0.558 27.877 ;
     RECT  45.18 27.103 47.25 27.877 ;
     RECT  0.108 27.877 0.558 28.013 ;
     RECT  42.804 27.751 43.182 28.219 ;
     RECT  82.08 27.751 84.654 28.219 ;
     RECT  0.144 28.013 0.558 28.253 ;
     RECT  10.764 28.147 10.782 28.283 ;
     RECT  45.18 27.877 47.538 28.291 ;
     RECT  7.815 27.821 8.262 28.561 ;
     RECT  9.036 28.183 9.126 28.561 ;
     RECT  2.268 27.599 5.778 28.685 ;
     RECT  6.624 27.821 7.002 28.687 ;
     RECT  7.815 28.561 9.126 28.687 ;
     RECT  44.208 28.183 44.226 28.723 ;
     RECT  45.036 28.291 47.538 28.723 ;
     RECT  6.624 28.687 9.126 28.751 ;
     RECT  40.215 2.413 40.497 28.831 ;
     RECT  81.54 28.219 84.654 28.831 ;
     RECT  44.208 28.723 47.538 29.029 ;
     RECT  49.356 27.031 49.374 29.101 ;
     RECT  2.304 28.685 5.778 29.191 ;
     RECT  6.624 28.751 8.586 29.191 ;
     RECT  44.208 29.029 48.186 29.191 ;
     RECT  49.356 29.101 49.554 29.191 ;
     RECT  42.3 28.219 43.182 29.227 ;
     RECT  2.304 29.191 8.586 29.291 ;
     RECT  0.468 28.253 0.558 29.335 ;
     RECT  80.388 29.029 80.406 29.371 ;
     RECT  81.504 28.831 84.654 29.371 ;
     RECT  10.8 29.227 10.818 29.399 ;
     RECT  0.18 29.335 0.558 29.453 ;
     RECT  42.192 29.227 43.182 29.533 ;
     RECT  44.208 29.191 49.554 29.533 ;
     RECT  40.215 28.831 40.986 29.569 ;
     RECT  0.18 29.453 0.342 29.605 ;
     RECT  40.215 29.569 41.094 29.767 ;
     RECT  42.192 29.533 49.554 29.795 ;
     RECT  0.108 29.605 0.342 29.837 ;
     RECT  40.215 29.767 41.382 29.911 ;
     RECT  42.192 29.795 47.358 29.911 ;
     RECT  81.504 29.371 84.906 29.995 ;
     RECT  0.18 29.837 0.198 30.125 ;
     RECT  81.504 29.995 85.482 30.125 ;
     RECT  48.168 29.795 49.554 30.181 ;
     RECT  2.304 29.291 8.226 30.187 ;
     RECT  48.168 30.181 49.626 30.187 ;
     RECT  50.544 27.841 51.858 30.187 ;
     RECT  84.888 30.125 85.482 30.209 ;
     RECT  85.428 30.209 85.482 30.221 ;
     RECT  2.232 30.187 8.226 30.271 ;
     RECT  78.015 27.779 78.297 30.307 ;
     RECT  81.504 30.125 84.078 30.307 ;
     RECT  48.168 30.187 51.858 30.407 ;
     RECT  2.232 30.271 8.478 30.451 ;
     RECT  10.98 30.451 11.07 30.541 ;
     RECT  40.215 29.911 47.358 30.541 ;
     RECT  48.168 30.407 51.297 30.541 ;
     RECT  79.848 29.371 80.406 30.568 ;
     RECT  81.396 30.307 84.078 30.569 ;
     RECT  2.232 30.451 8.514 30.571 ;
     RECT  9.396 30.415 9.414 30.571 ;
     RECT  10.908 30.541 11.07 30.605 ;
     RECT  10.908 30.605 10.926 30.641 ;
     RECT  78.015 30.307 78.678 30.649 ;
     RECT  2.232 30.571 9.414 30.677 ;
     RECT  2.232 30.677 8.478 30.749 ;
     RECT  79.848 30.568 80.658 30.811 ;
     RECT  81.396 30.569 83.97 30.811 ;
     RECT  79.848 30.811 83.97 30.947 ;
     RECT  78.015 30.649 78.75 30.955 ;
     RECT  2.232 30.749 6.93 31.003 ;
     RECT  0.144 30.763 0.162 31.037 ;
     RECT  1.728 31.003 6.93 31.037 ;
     RECT  7.704 30.749 8.478 31.181 ;
     RECT  80.388 30.947 83.97 31.181 ;
     RECT  0.216 31.051 0.234 31.229 ;
     RECT  1.728 31.037 6.894 31.253 ;
     RECT  9.252 30.677 9.414 31.351 ;
     RECT  1.728 31.253 5.418 31.649 ;
     RECT  6.228 31.253 6.894 31.649 ;
     RECT  81.216 31.181 83.97 31.649 ;
     RECT  9.252 31.351 9.702 31.657 ;
     RECT  6.66 31.649 6.894 31.685 ;
     RECT  78.015 30.955 78.786 31.693 ;
     RECT  6.84 31.685 6.894 31.757 ;
     RECT  9.252 31.657 10.422 31.757 ;
     RECT  38.772 30.811 38.79 31.757 ;
     RECT  85.464 30.221 85.482 31.765 ;
     RECT  9.252 31.757 9.81 31.801 ;
     RECT  84.924 31.765 85.482 31.801 ;
     RECT  9.216 31.801 9.81 31.819 ;
     RECT  6.876 31.757 6.894 31.829 ;
     RECT  78.015 31.693 78.822 31.829 ;
     RECT  84.924 31.801 85.554 31.891 ;
     RECT  86.292 31.729 86.31 31.891 ;
     RECT  1.728 31.649 4.338 31.919 ;
     RECT  7.815 31.181 8.298 31.919 ;
     RECT  1.728 31.919 2.898 32.027 ;
     RECT  52.092 31.999 52.11 32.035 ;
     RECT  40.215 30.541 51.297 32.071 ;
     RECT  52.056 32.035 52.11 32.071 ;
     RECT  3.708 31.919 4.338 32.189 ;
     RECT  2.304 32.027 2.898 32.225 ;
     RECT  40.215 32.071 52.11 32.269 ;
     RECT  80.388 31.181 80.406 32.269 ;
     RECT  81.396 31.649 83.97 32.269 ;
     RECT  84.924 31.891 86.31 32.269 ;
     RECT  9.072 31.819 9.81 32.333 ;
     RECT  5.112 31.649 5.418 32.341 ;
     RECT  81.396 32.269 86.31 32.342 ;
     RECT  5.112 32.341 5.706 32.369 ;
     RECT  40.215 32.269 52.146 32.459 ;
     RECT  54.612 32.341 54.702 32.459 ;
     RECT  9.072 32.333 9.702 32.491 ;
     RECT  54.684 32.459 54.702 32.495 ;
     RECT  40.215 32.459 51.786 32.525 ;
     RECT  78.015 31.829 78.786 32.639 ;
     RECT  2.415 32.225 2.898 32.701 ;
     RECT  3.708 32.189 4.266 32.701 ;
     RECT  78.015 32.639 78.75 32.837 ;
     RECT  5.688 32.369 5.706 32.845 ;
     RECT  7.815 31.919 8.097 32.881 ;
     RECT  80.388 32.269 80.622 32.881 ;
     RECT  81.396 32.342 85.518 32.881 ;
     RECT  78.015 32.837 78.678 32.909 ;
     RECT  2.415 32.701 4.266 32.971 ;
     RECT  7.308 32.881 8.097 32.971 ;
     RECT  8.82 32.491 9.702 32.999 ;
     RECT  80.388 32.881 85.518 32.999 ;
     RECT  8.82 32.999 9.198 33.005 ;
     RECT  86.256 32.342 86.31 33.005 ;
     RECT  0.108 32.845 0.126 33.043 ;
     RECT  2.34 32.971 4.266 33.043 ;
     RECT  9.18 33.005 9.198 33.071 ;
     RECT  48.132 32.525 51.786 33.071 ;
     RECT  2.34 33.043 4.518 33.151 ;
     RECT  2.304 33.151 4.518 33.211 ;
     RECT  5.688 32.845 5.778 33.313 ;
     RECT  6.84 32.971 8.097 33.313 ;
     RECT  40.215 32.525 47.358 33.385 ;
     RECT  48.132 33.071 51.297 33.385 ;
     RECT  0.108 33.043 0.162 33.421 ;
     RECT  5.688 33.313 5.85 33.421 ;
     RECT  6.84 33.313 8.406 33.421 ;
     RECT  86.292 33.005 86.31 33.485 ;
     RECT  2.304 33.211 4.77 33.583 ;
     RECT  38.808 33.619 38.826 33.655 ;
     RECT  0.108 33.421 0.558 33.773 ;
     RECT  80.604 32.999 85.518 33.869 ;
     RECT  38.772 33.655 38.826 33.889 ;
     RECT  2.304 33.583 4.914 33.925 ;
     RECT  5.688 33.421 8.406 33.925 ;
     RECT  80.604 33.869 84.114 33.961 ;
     RECT  9.216 33.889 9.234 33.989 ;
     RECT  0.144 33.773 0.558 34.061 ;
     RECT  2.304 33.925 8.406 34.151 ;
     RECT  80.496 33.961 84.114 34.159 ;
     RECT  7.815 34.151 8.406 34.195 ;
     RECT  79.812 34.159 84.114 34.253 ;
     RECT  10.728 34.231 10.818 34.349 ;
     RECT  38.772 33.889 38.862 34.349 ;
     RECT  40.215 33.385 51.297 34.393 ;
     RECT  10.728 34.349 10.782 34.457 ;
     RECT  40.215 34.393 51.318 34.457 ;
     RECT  46.656 34.457 51.318 34.501 ;
     RECT  52.992 34.393 53.01 34.501 ;
     RECT  84.888 33.869 85.518 34.603 ;
     RECT  38.844 34.349 38.862 34.619 ;
     RECT  52.344 34.501 53.01 34.663 ;
     RECT  56.415 2.413 56.697 34.663 ;
     RECT  54.684 34.501 54.702 34.735 ;
     RECT  55.476 34.663 56.697 34.735 ;
     RECT  84.852 34.603 85.518 34.735 ;
     RECT  2.304 34.151 7.002 34.763 ;
     RECT  7.815 34.195 8.91 34.771 ;
     RECT  52.164 34.663 53.01 34.771 ;
     RECT  54.684 34.735 56.697 34.771 ;
     RECT  0.144 34.061 0.162 34.795 ;
     RECT  0.144 34.795 0.342 34.816 ;
     RECT  0.108 34.816 0.342 34.844 ;
     RECT  7.815 34.771 9.09 34.889 ;
     RECT  84.852 34.735 85.554 34.891 ;
     RECT  46.656 34.501 51.39 34.897 ;
     RECT  52.164 34.771 53.838 34.897 ;
     RECT  54.684 34.771 57.114 34.897 ;
     RECT  78.015 32.909 78.297 34.897 ;
     RECT  0.108 34.844 0.234 34.925 ;
     RECT  79.812 34.253 83.898 34.961 ;
     RECT  7.815 34.889 8.946 34.997 ;
     RECT  79.812 34.961 83.826 34.997 ;
     RECT  84.816 34.891 85.554 35.117 ;
     RECT  78.015 34.897 78.75 35.131 ;
     RECT  10.764 34.457 10.782 35.159 ;
     RECT  1.152 35.083 1.17 35.275 ;
     RECT  46.656 34.897 57.186 35.437 ;
     RECT  46.656 35.437 57.258 35.465 ;
     RECT  2.304 34.763 6.93 35.467 ;
     RECT  2.268 35.467 6.93 35.563 ;
     RECT  2.232 35.563 6.93 35.609 ;
     RECT  54.468 35.465 57.258 35.671 ;
     RECT  7.815 34.997 8.334 35.699 ;
     RECT  46.656 35.465 53.658 35.699 ;
     RECT  4.14 35.609 6.93 35.735 ;
     RECT  80.604 34.997 83.826 35.755 ;
     RECT  84.816 35.117 85.482 35.755 ;
     RECT  54.468 35.671 57.294 35.771 ;
     RECT  40.215 34.457 45.897 35.779 ;
     RECT  46.656 35.699 49.014 35.779 ;
     RECT  86.292 35.563 86.31 35.807 ;
     RECT  54.468 35.771 57.222 35.843 ;
     RECT  54.468 35.843 55.638 35.879 ;
     RECT  56.415 35.843 57.222 35.879 ;
     RECT  2.232 35.609 3.33 36.005 ;
     RECT  80.604 35.755 85.482 36.013 ;
     RECT  40.215 35.779 49.014 36.041 ;
     RECT  49.788 35.699 53.658 36.077 ;
     RECT  80.388 36.013 85.482 36.121 ;
     RECT  52.524 36.077 53.658 36.247 ;
     RECT  80.172 36.121 85.482 36.275 ;
     RECT  52.524 36.247 53.73 36.319 ;
     RECT  54.468 35.879 54.954 36.319 ;
     RECT  13.215 2.413 13.497 36.355 ;
     RECT  49.788 36.077 51.426 36.383 ;
     RECT  52.524 36.319 54.954 36.383 ;
     RECT  78.015 35.131 79.254 36.509 ;
     RECT  13.14 36.355 13.497 36.619 ;
     RECT  79.236 36.509 79.254 36.625 ;
     RECT  52.524 36.383 54.63 36.653 ;
     RECT  4.14 35.735 6.282 36.661 ;
     RECT  41.436 36.041 49.014 36.661 ;
     RECT  49.788 36.383 51.318 36.661 ;
     RECT  0.108 36.523 0.126 36.715 ;
     RECT  24.015 2.413 24.297 36.751 ;
     RECT  34.815 2.413 35.097 36.751 ;
     RECT  23.904 36.751 24.297 36.797 ;
     RECT  34.704 36.751 35.097 36.797 ;
     RECT  41.436 36.661 51.318 36.815 ;
     RECT  4.14 36.661 6.822 36.823 ;
     RECT  0.108 36.715 0.342 36.845 ;
     RECT  4.14 36.823 7.002 36.851 ;
     RECT  52.524 36.653 54.558 36.859 ;
     RECT  41.544 36.815 51.318 36.887 ;
     RECT  52.056 36.859 54.558 36.887 ;
     RECT  7.815 35.699 8.097 36.895 ;
     RECT  2.304 36.005 3.33 36.931 ;
     RECT  4.14 36.851 5.922 36.931 ;
     RECT  2.304 36.931 5.922 37.049 ;
     RECT  6.696 36.851 7.002 37.049 ;
     RECT  7.776 36.895 8.097 37.049 ;
     RECT  2.304 37.049 3.762 37.085 ;
     RECT  6.804 37.049 6.894 37.085 ;
     RECT  41.58 36.887 51.318 37.085 ;
     RECT  5.76 37.049 5.922 37.133 ;
     RECT  52.056 36.887 54.27 37.157 ;
     RECT  1.152 35.275 1.206 37.193 ;
     RECT  6.84 37.085 6.894 37.193 ;
     RECT  41.832 37.085 51.318 37.201 ;
     RECT  9.288 37.165 9.306 37.319 ;
     RECT  41.832 37.201 51.894 37.319 ;
     RECT  52.668 37.157 54.27 37.319 ;
     RECT  41.832 37.319 51.75 37.325 ;
     RECT  12.456 36.619 13.497 37.328 ;
     RECT  53.064 37.319 54.27 37.342 ;
     RECT  2.34 37.085 3.762 37.355 ;
     RECT  12.456 37.328 12.474 37.355 ;
     RECT  78.015 36.509 78.297 37.363 ;
     RECT  79.236 36.625 79.506 37.363 ;
     RECT  41.832 37.325 51.678 37.391 ;
     RECT  7.815 37.049 8.097 37.435 ;
     RECT  78.015 37.363 79.506 37.463 ;
     RECT  6.876 37.193 6.894 37.469 ;
     RECT  7.815 37.435 8.37 37.472 ;
     RECT  80.388 36.275 85.482 37.516 ;
     RECT  2.376 37.355 3.762 37.589 ;
     RECT  7.815 37.472 8.226 37.589 ;
     RECT  10.8 37.435 10.818 37.589 ;
     RECT  41.832 37.391 51.297 37.589 ;
     RECT  53.496 37.342 54.27 37.589 ;
     RECT  80.388 37.516 85.518 37.613 ;
     RECT  1.152 37.193 1.17 37.625 ;
     RECT  50.976 37.589 51.297 37.625 ;
     RECT  54.18 37.589 54.27 37.625 ;
     RECT  80.388 37.613 85.482 37.769 ;
     RECT  5.904 37.133 5.922 37.859 ;
     RECT  41.832 37.589 50.094 37.859 ;
     RECT  2.376 37.589 3.078 37.895 ;
     RECT  41.832 37.859 49.122 37.963 ;
     RECT  41.58 37.963 49.122 38.003 ;
     RECT  4.536 37.049 4.95 38.129 ;
     RECT  45.072 38.003 49.122 38.129 ;
     RECT  79.236 37.463 79.506 38.129 ;
     RECT  85.428 37.769 85.482 38.129 ;
     RECT  2.415 37.895 3.078 38.165 ;
     RECT  86.292 37.021 86.31 38.173 ;
     RECT  41.58 38.003 44.262 38.201 ;
     RECT  78.015 37.463 78.297 38.281 ;
     RECT  41.58 38.201 42.066 38.399 ;
     RECT  42.84 38.201 44.262 38.399 ;
     RECT  78.015 38.281 78.678 38.399 ;
     RECT  4.932 38.129 4.95 38.435 ;
     RECT  9.036 38.443 9.054 38.48 ;
     RECT  80.388 37.769 84.654 38.579 ;
     RECT  2.415 38.165 3.006 38.635 ;
     RECT  2.304 38.635 3.006 38.669 ;
     RECT  41.4 38.515 41.418 38.669 ;
     RECT  85.428 38.129 85.446 38.669 ;
     RECT  20.7 38.539 20.718 38.705 ;
     RECT  43.056 38.399 44.262 38.741 ;
     RECT  43.344 38.741 44.262 38.821 ;
     RECT  45.072 38.129 48.69 38.821 ;
     RECT  43.344 38.821 48.69 38.939 ;
     RECT  2.304 38.669 2.697 38.975 ;
     RECT  43.344 38.939 43.362 39.083 ;
     RECT  44.1 38.939 48.69 39.091 ;
     RECT  44.1 39.091 48.834 39.209 ;
     RECT  44.136 39.209 48.834 39.307 ;
     RECT  44.136 39.307 48.906 39.595 ;
     RECT  44.136 39.595 49.014 39.631 ;
     RECT  50.076 37.859 50.094 39.631 ;
     RECT  44.136 39.631 50.094 39.749 ;
     RECT  44.136 39.749 49.014 39.785 ;
     RECT  44.136 39.785 48.906 39.869 ;
     RECT  44.136 39.869 48.69 40.019 ;
     RECT  44.136 40.019 48.582 40.135 ;
     RECT  44.1 40.135 48.582 40.171 ;
     RECT  43.452 40.171 48.582 40.289 ;
     RECT  44.1 40.289 48.582 40.325 ;
     RECT  44.136 40.325 48.582 40.361 ;
     RECT  80.964 38.579 84.654 40.361 ;
     RECT  44.568 40.361 48.582 40.397 ;
     RECT  43.272 40.369 43.29 40.445 ;
     RECT  44.568 40.397 44.838 40.559 ;
     RECT  81.684 40.361 84.654 40.559 ;
     RECT  44.568 40.559 44.586 40.595 ;
     RECT  45.615 40.397 48.582 40.829 ;
     RECT  79.488 38.129 79.506 40.829 ;
     RECT  86.292 38.173 86.382 40.829 ;
     RECT  81.756 40.559 84.654 41.009 ;
     RECT  86.364 40.829 86.382 41.009 ;
     RECT  47.088 40.829 48.582 41.369 ;
     RECT  82.368 41.009 84.654 41.369 ;
     RECT  45.615 40.829 45.897 41.611 ;
     RECT  82.368 41.369 83.79 41.639 ;
     RECT  45.615 41.611 46.134 41.791 ;
     RECT  84.636 41.369 84.654 41.909 ;
     RECT  82.368 41.639 83.697 41.945 ;
     RECT  45.615 41.791 46.17 42.173 ;
     RECT  82.368 41.945 82.53 42.179 ;
     RECT  29.415 2.413 29.697 43.915 ;
     RECT  45.615 42.173 45.897 43.915 ;
     RECT  18.615 2.413 18.897 44.059 ;
     RECT  24.015 36.797 24.297 44.059 ;
     RECT  29.415 43.915 29.754 44.059 ;
     RECT  34.815 36.797 35.097 44.059 ;
     RECT  40.215 36.041 40.497 44.059 ;
     RECT  45.615 43.915 46.422 44.069 ;
     RECT  18.615 44.059 18.99 44.105 ;
     RECT  24.015 44.059 24.39 44.105 ;
     RECT  34.815 44.059 35.19 44.105 ;
     RECT  40.215 44.059 40.59 44.105 ;
     RECT  47.196 41.369 48.582 44.221 ;
     RECT  29.415 44.059 30.006 44.249 ;
     RECT  46.728 44.221 48.582 44.285 ;
     RECT  47.196 44.285 48.582 51.307 ;
     RECT  47.124 51.307 48.582 51.359 ;
     RECT  47.196 51.359 48.582 58.531 ;
     RECT  47.196 58.531 48.618 58.699 ;
     RECT  47.196 58.699 48.87 58.757 ;
     RECT  48.24 58.757 48.87 59.035 ;
     RECT  48.24 59.035 49.158 59.071 ;
     RECT  50.076 39.749 50.094 59.071 ;
     RECT  48.24 59.071 50.094 59.467 ;
     RECT  51.015 37.625 51.297 59.467 ;
     RECT  47.196 58.757 47.394 59.611 ;
     RECT  48.24 59.467 51.297 59.611 ;
     RECT  45.615 44.069 45.897 60.349 ;
     RECT  47.196 59.611 51.297 60.349 ;
     RECT  45.615 60.349 51.297 60.461 ;
     RECT  46.764 60.461 51.297 60.539 ;
     RECT  45.615 60.461 45.897 61.231 ;
     RECT  46.944 60.539 51.297 61.349 ;
     RECT  45.615 61.231 46.206 61.387 ;
     RECT  46.944 61.349 50.274 61.387 ;
     RECT  45.615 61.387 50.274 61.763 ;
     RECT  45.615 61.763 46.422 61.889 ;
     RECT  47.196 61.763 50.274 61.889 ;
     RECT  47.196 61.889 50.166 61.925 ;
     RECT  47.196 61.925 50.094 62.069 ;
     RECT  47.592 62.069 50.094 62.159 ;
     RECT  47.772 62.159 50.094 62.231 ;
     RECT  2.415 38.975 2.697 62.387 ;
     RECT  7.815 37.589 8.097 62.387 ;
     RECT  13.215 37.328 13.497 62.387 ;
     RECT  18.615 44.105 18.897 62.387 ;
     RECT  24.015 44.105 24.297 62.387 ;
     RECT  29.415 44.249 29.697 62.387 ;
     RECT  34.815 44.105 35.097 62.387 ;
     RECT  40.215 44.105 40.497 62.387 ;
     RECT  45.615 61.889 45.897 62.387 ;
     RECT  51.015 61.349 51.297 62.387 ;
     RECT  56.415 35.879 56.697 62.387 ;
     RECT  61.815 2.413 62.097 62.387 ;
     RECT  67.215 2.413 67.497 62.387 ;
     RECT  72.615 2.413 72.897 62.387 ;
     RECT  78.015 38.399 78.297 62.387 ;
     RECT  83.415 41.945 83.697 62.387 ;
     RECT  47.88 62.231 50.094 62.429 ;
     RECT  2.415 62.387 2.505 62.657 ;
     RECT  7.815 62.387 7.905 62.657 ;
     RECT  13.215 62.387 13.305 62.657 ;
     RECT  18.615 62.387 18.705 62.657 ;
     RECT  24.015 62.387 24.105 62.657 ;
     RECT  29.415 62.387 29.505 62.657 ;
     RECT  34.815 62.387 34.905 62.657 ;
     RECT  40.215 62.387 40.305 62.657 ;
     RECT  45.615 62.387 45.705 62.657 ;
     RECT  51.015 62.387 51.105 62.657 ;
     RECT  56.415 62.387 56.505 62.657 ;
     RECT  61.815 62.387 61.905 62.657 ;
     RECT  67.215 62.387 67.305 62.657 ;
     RECT  72.615 62.387 72.705 62.657 ;
     RECT  78.015 62.387 78.105 62.657 ;
     RECT  83.415 62.387 83.505 62.657 ;
     RECT  48.24 62.429 50.094 62.669 ;
     RECT  48.24 62.669 50.022 62.717 ;
     RECT  48.24 62.717 49.446 63.293 ;
     RECT  48.24 63.293 48.978 63.869 ;
     RECT  49.104 64.315 49.338 64.411 ;
     RECT  49.104 64.411 49.482 64.589 ;
     RECT  49.176 64.589 49.482 64.685 ;
    LAYER M4 ;
     RECT  0.06 33.456 0.097 35.592 ;
     RECT  0.06 36.624 0.097 37.128 ;
     RECT  0.06 26.448 0.137 31.272 ;
     RECT  0.097 33.456 2.293 37.128 ;
     RECT  0.137 26.544 2.408 31.272 ;
     RECT  2.293 33.36 2.408 37.128 ;
     RECT  0.06 38.544 2.408 38.664 ;
     RECT  0.181 43.92 2.408 43.944 ;
     RECT  2.408 2.148 2.512 62.652 ;
     RECT  2.512 2.418 2.704 62.382 ;
     RECT  2.704 28.224 2.801 31.656 ;
     RECT  2.704 36.912 2.801 37.128 ;
     RECT  2.704 26.832 2.837 26.856 ;
     RECT  2.704 33.36 2.837 35.88 ;
     RECT  2.801 28.224 2.945 30.6 ;
     RECT  2.801 36.912 3.089 36.936 ;
     RECT  2.837 34.416 3.125 35.88 ;
     RECT  2.945 29.664 3.539 30.6 ;
     RECT  3.125 35.376 3.701 35.88 ;
     RECT  3.539 29.664 3.913 29.688 ;
     RECT  3.913 29.568 3.953 29.688 ;
     RECT  2.945 28.224 4.237 28.248 ;
     RECT  4.129 26.784 4.309 26.808 ;
     RECT  2.801 31.632 4.501 31.656 ;
     RECT  3.877 33.792 4.525 33.816 ;
     RECT  4.525 33.792 4.597 34.344 ;
     RECT  4.237 27.84 4.604 28.248 ;
     RECT  4.501 30.816 4.643 31.656 ;
     RECT  4.597 33.216 4.643 34.344 ;
     RECT  4.604 27.792 4.669 28.248 ;
     RECT  3.953 29.568 4.669 29.64 ;
     RECT  4.643 33.216 4.781 33.816 ;
     RECT  4.669 27.792 4.993 29.64 ;
     RECT  4.643 30.816 4.993 31.368 ;
     RECT  4.309 26.688 5.173 26.808 ;
     RECT  4.993 27.792 5.173 31.368 ;
     RECT  3.701 35.856 5.425 35.88 ;
     RECT  4.561 37.008 5.425 37.032 ;
     RECT  5.425 35.856 5.605 37.032 ;
     RECT  5.605 35.328 5.713 37.032 ;
     RECT  5.713 34.896 5.749 37.032 ;
     RECT  4.781 33.792 5.948 33.816 ;
     RECT  5.948 33.648 5.965 33.816 ;
     RECT  5.749 34.896 5.965 37.128 ;
     RECT  5.965 33.648 6.131 37.128 ;
     RECT  5.173 26.688 6.323 31.368 ;
     RECT  6.323 27.168 6.721 31.368 ;
     RECT  6.721 27.168 6.853 31.416 ;
     RECT  6.131 36.48 6.865 37.128 ;
     RECT  6.853 27.168 6.901 31.464 ;
     RECT  6.901 27.168 7.808 31.944 ;
     RECT  6.131 33.648 7.808 34.92 ;
     RECT  6.865 36.48 7.808 37.464 ;
     RECT  2.704 38.544 7.808 38.568 ;
     RECT  2.704 43.92 7.808 43.944 ;
     RECT  7.808 2.148 7.912 62.652 ;
     RECT  7.912 2.418 8.104 62.382 ;
     RECT  8.104 26.496 8.165 27.192 ;
     RECT  8.165 26.496 8.243 26.52 ;
     RECT  8.104 30.336 8.291 35.016 ;
     RECT  8.104 36.24 8.381 37.464 ;
     RECT  8.291 34.368 8.417 35.016 ;
     RECT  8.291 30.336 8.453 33 ;
     RECT  8.453 30.384 9.148 33 ;
     RECT  9.148 30.384 9.713 32.52 ;
     RECT  9.713 32.304 9.821 32.328 ;
     RECT  8.104 28.224 13.208 28.248 ;
     RECT  9.713 30.384 13.208 30.696 ;
     RECT  8.417 34.992 13.208 35.016 ;
     RECT  8.381 36.24 13.208 37.32 ;
     RECT  8.104 38.448 13.208 38.568 ;
     RECT  8.104 43.92 13.208 43.944 ;
     RECT  13.208 2.148 13.312 62.652 ;
     RECT  13.312 2.418 13.504 62.382 ;
     RECT  13.504 36.624 13.667 36.888 ;
     RECT  13.504 28.224 18.608 28.248 ;
     RECT  13.504 30.384 18.608 30.696 ;
     RECT  13.504 34.992 18.608 35.016 ;
     RECT  13.667 36.768 18.608 36.888 ;
     RECT  13.504 38.448 18.608 38.568 ;
     RECT  13.504 43.92 18.608 44.088 ;
     RECT  18.608 2.148 18.712 62.652 ;
     RECT  18.712 2.418 18.904 62.382 ;
     RECT  18.904 38.448 20.729 38.568 ;
     RECT  18.904 28.224 24.008 28.248 ;
     RECT  18.904 30.384 24.008 30.696 ;
     RECT  18.904 34.992 24.008 35.016 ;
     RECT  18.904 36.768 24.008 36.888 ;
     RECT  20.729 38.448 24.008 38.472 ;
     RECT  18.904 43.92 24.008 44.088 ;
     RECT  24.008 2.148 24.112 62.652 ;
     RECT  24.112 2.418 24.304 62.382 ;
     RECT  24.304 28.224 29.408 28.248 ;
     RECT  24.304 30.384 29.408 30.696 ;
     RECT  24.304 34.992 29.408 35.016 ;
     RECT  24.304 36.768 29.408 36.888 ;
     RECT  24.304 38.448 29.408 38.472 ;
     RECT  24.304 43.92 29.408 44.088 ;
     RECT  29.408 2.148 29.512 62.652 ;
     RECT  29.512 2.418 29.704 62.382 ;
     RECT  29.704 43.92 29.765 44.184 ;
     RECT  29.765 44.064 30.017 44.184 ;
     RECT  29.704 28.224 34.808 28.248 ;
     RECT  29.704 30.384 34.808 30.696 ;
     RECT  29.704 34.992 34.808 35.016 ;
     RECT  29.704 36.768 34.808 36.888 ;
     RECT  29.704 38.448 34.808 38.472 ;
     RECT  30.017 44.064 34.808 44.088 ;
     RECT  34.808 2.148 34.912 62.652 ;
     RECT  34.912 2.418 35.104 62.382 ;
     RECT  35.104 28.224 40.208 28.248 ;
     RECT  35.104 30.384 40.208 30.696 ;
     RECT  35.104 34.992 40.208 35.016 ;
     RECT  35.104 36.768 40.208 36.888 ;
     RECT  35.104 38.448 40.208 38.472 ;
     RECT  35.104 44.064 40.208 44.088 ;
     RECT  40.208 2.148 40.312 62.652 ;
     RECT  40.312 2.418 40.504 62.382 ;
     RECT  40.504 36.768 41.569 36.888 ;
     RECT  40.504 37.872 41.569 38.472 ;
     RECT  41.533 32.208 41.605 32.232 ;
     RECT  40.504 33.552 41.929 33.576 ;
     RECT  40.504 30.384 41.965 30.696 ;
     RECT  40.504 34.992 42.145 35.016 ;
     RECT  41.569 36.768 42.145 38.472 ;
     RECT  40.504 28.224 42.329 28.248 ;
     RECT  41.965 30.384 42.721 30.888 ;
     RECT  41.929 33.552 42.721 34.008 ;
     RECT  42.145 34.992 42.721 38.472 ;
     RECT  42.721 30.384 42.941 30.936 ;
     RECT  41.605 32.208 43.045 32.472 ;
     RECT  42.941 30.384 43.657 30.792 ;
     RECT  42.721 33.552 43.913 38.472 ;
     RECT  43.913 33.552 43.985 36.888 ;
     RECT  43.913 37.872 44.125 38.472 ;
     RECT  43.657 30.192 44.377 30.792 ;
     RECT  43.045 32.064 44.377 32.472 ;
     RECT  44.125 37.872 44.593 38.808 ;
     RECT  44.377 30.192 44.821 32.472 ;
     RECT  44.593 37.872 45.164 39.336 ;
     RECT  43.261 40.416 45.164 40.44 ;
     RECT  43.985 34.656 45.205 36.888 ;
     RECT  45.164 37.872 45.205 40.44 ;
     RECT  40.504 44.064 45.205 44.088 ;
     RECT  44.821 30.048 45.277 32.472 ;
     RECT  43.985 33.552 45.277 33.576 ;
     RECT  45.205 34.656 45.493 40.44 ;
     RECT  45.277 30.048 45.608 33.576 ;
     RECT  45.493 34.656 45.608 40.68 ;
     RECT  45.205 43.92 45.608 44.088 ;
     RECT  45.608 2.148 45.712 62.652 ;
     RECT  45.712 2.418 45.904 62.382 ;
     RECT  45.904 30.048 46.067 33.672 ;
     RECT  45.904 41.856 46.156 42.168 ;
     RECT  45.904 60.432 46.289 61.752 ;
     RECT  45.904 43.92 46.433 44.28 ;
     RECT  46.156 42.144 46.739 42.168 ;
     RECT  46.433 44.256 46.757 44.28 ;
     RECT  45.904 34.8 46.865 38.136 ;
     RECT  46.067 30.048 47.077 32.856 ;
     RECT  45.904 51.312 47.153 51.336 ;
     RECT  46.289 60.432 47.269 61.416 ;
     RECT  47.077 29.424 47.297 32.856 ;
     RECT  47.269 60.336 47.315 61.416 ;
     RECT  47.297 32.256 47.372 32.856 ;
     RECT  47.372 32.256 47.459 33.528 ;
     RECT  47.315 60.336 47.509 60.792 ;
     RECT  46.865 38.112 47.516 38.136 ;
     RECT  45.904 39.216 47.516 40.68 ;
     RECT  47.297 29.424 47.873 31.128 ;
     RECT  47.509 59.76 47.891 60.792 ;
     RECT  47.873 30.144 48.265 31.128 ;
     RECT  47.459 32.256 48.265 32.856 ;
     RECT  48.229 58.704 48.277 58.728 ;
     RECT  47.891 59.76 48.277 60.36 ;
     RECT  46.865 34.848 48.301 37.08 ;
     RECT  47.516 38.112 48.301 40.68 ;
     RECT  48.229 51.84 48.313 51.864 ;
     RECT  48.277 58.704 48.364 60.36 ;
     RECT  48.364 59.712 48.485 60.36 ;
     RECT  48.301 34.848 48.515 40.68 ;
     RECT  48.515 34.848 48.517 37.944 ;
     RECT  48.476 62.736 48.625 62.76 ;
     RECT  48.265 30.144 48.697 32.856 ;
     RECT  48.625 62.448 48.805 62.76 ;
     RECT  48.517 34.8 48.899 37.944 ;
     RECT  48.515 39.312 48.899 40.68 ;
     RECT  48.899 39.312 48.917 39.864 ;
     RECT  48.805 62.16 48.917 62.76 ;
     RECT  48.364 58.704 48.925 58.728 ;
     RECT  48.917 39.84 48.94 39.864 ;
     RECT  48.229 63.84 48.997 63.864 ;
     RECT  48.997 63.84 49.093 64.488 ;
     RECT  49.093 63.84 49.138 64.584 ;
     RECT  49.138 63.84 49.139 64.68 ;
     RECT  49.139 64.32 49.349 64.68 ;
     RECT  48.697 30.144 49.385 33.048 ;
     RECT  48.917 62.304 49.417 62.76 ;
     RECT  49.385 30.144 49.475 32.856 ;
     RECT  49.349 64.416 49.493 64.68 ;
     RECT  49.493 64.656 49.537 64.68 ;
     RECT  48.899 34.8 49.573 37.608 ;
     RECT  49.417 62.304 49.619 63.288 ;
     RECT  49.619 62.304 49.715 62.712 ;
     RECT  48.485 59.712 49.717 59.784 ;
     RECT  49.717 59.712 49.889 60.456 ;
     RECT  49.475 30.192 49.997 32.856 ;
     RECT  49.715 62.544 50.033 62.712 ;
     RECT  50.033 62.544 50.105 62.664 ;
     RECT  49.997 32.256 50.641 32.856 ;
     RECT  50.641 32.256 50.857 33 ;
     RECT  49.997 30.192 51.008 30.744 ;
     RECT  50.857 32.256 51.008 33.576 ;
     RECT  49.573 34.752 51.008 37.608 ;
     RECT  49.889 59.712 51.008 59.736 ;
     RECT  50.105 62.544 51.008 62.652 ;
     RECT  51.008 2.148 51.112 62.652 ;
     RECT  51.112 2.418 51.304 62.382 ;
     RECT  51.304 34.992 52.553 37.608 ;
     RECT  52.553 36.912 53.057 37.608 ;
     RECT  53.057 37.296 53.093 37.608 ;
     RECT  53.093 37.584 54.281 37.608 ;
     RECT  52.553 34.992 54.933 35.448 ;
     RECT  54.933 34.752 55.041 35.448 ;
     RECT  51.304 30.576 56.408 30.696 ;
     RECT  51.304 32.256 56.408 32.28 ;
     RECT  55.041 34.752 56.408 35.832 ;
     RECT  56.408 2.148 56.512 62.652 ;
     RECT  56.512 2.418 56.704 62.382 ;
     RECT  56.704 30.576 61.808 30.696 ;
     RECT  56.704 32.256 61.808 32.28 ;
     RECT  61.808 2.148 61.912 62.652 ;
     RECT  61.912 2.418 62.104 62.382 ;
     RECT  62.104 30.576 67.208 30.696 ;
     RECT  62.104 32.256 67.208 32.28 ;
     RECT  67.208 2.148 67.312 62.652 ;
     RECT  67.312 2.418 67.504 62.382 ;
     RECT  67.504 30.576 72.608 30.696 ;
     RECT  67.504 32.256 72.608 32.28 ;
     RECT  72.608 2.148 72.712 62.652 ;
     RECT  72.712 2.418 72.904 62.382 ;
     RECT  72.904 30.576 78.008 30.696 ;
     RECT  72.904 32.256 78.008 32.28 ;
     RECT  78.008 2.148 78.112 62.652 ;
     RECT  78.112 2.418 78.304 62.382 ;
     RECT  78.304 30.576 80.669 30.696 ;
     RECT  80.669 30.672 81.533 30.696 ;
     RECT  82.537 37.104 82.645 37.128 ;
     RECT  81.781 35.04 82.897 35.064 ;
     RECT  78.304 32.256 83.408 32.28 ;
     RECT  83.365 33.36 83.408 33.384 ;
     RECT  82.897 34.656 83.408 35.064 ;
     RECT  82.645 37.008 83.408 37.128 ;
     RECT  82.429 41.616 83.408 41.64 ;
     RECT  83.408 2.148 83.512 62.652 ;
     RECT  83.512 2.418 83.704 62.382 ;
     RECT  83.704 29.136 85.417 30.12 ;
     RECT  83.704 32.496 85.417 37.896 ;
     RECT  85.417 32.4 85.453 38.088 ;
     RECT  85.453 32.208 86.281 38.088 ;
     RECT  85.417 29.136 86.364 30.216 ;
     RECT  86.281 32.208 86.364 38.28 ;
    LAYER M5 ;
     RECT  2.4 2.137 2.52 2.151 ;
     RECT  7.8 2.137 7.92 2.151 ;
     RECT  13.2 2.137 13.32 2.151 ;
     RECT  18.6 2.137 18.72 2.151 ;
     RECT  24 2.137 24.12 2.151 ;
     RECT  29.4 2.137 29.52 2.151 ;
     RECT  34.8 2.137 34.92 2.151 ;
     RECT  40.2 2.137 40.32 2.151 ;
     RECT  45.6 2.137 45.72 2.151 ;
     RECT  51 2.137 51.12 2.151 ;
     RECT  56.4 2.137 56.52 2.151 ;
     RECT  61.8 2.137 61.92 2.151 ;
     RECT  67.2 2.137 67.32 2.151 ;
     RECT  72.6 2.137 72.72 2.151 ;
     RECT  78 2.137 78.12 2.151 ;
     RECT  83.4 2.137 83.52 2.151 ;
     RECT  7.8 2.151 8.112 26.485 ;
     RECT  6.288 26.677 6.312 27.157 ;
     RECT  7.8 26.485 8.232 27.157 ;
     RECT  5.616 27.157 6.312 27.781 ;
     RECT  7.68 27.157 8.232 27.781 ;
     RECT  4.656 27.781 8.232 27.877 ;
     RECT  4.512 27.877 8.232 29.603 ;
     RECT  2.4 2.151 2.712 29.653 ;
     RECT  45.6 2.151 45.912 30.037 ;
     RECT  47.616 29.605 47.64 30.179 ;
     RECT  5.616 29.603 8.232 30.323 ;
     RECT  6 30.323 8.232 30.469 ;
     RECT  49.44 30.133 49.464 30.517 ;
     RECT  2.4 29.653 3.528 30.611 ;
     RECT  48.864 30.517 49.464 30.661 ;
     RECT  44.832 30.037 45.912 31.093 ;
     RECT  46.944 30.613 46.968 31.093 ;
     RECT  44.832 31.093 46.968 31.379 ;
     RECT  48.72 30.661 49.464 31.571 ;
     RECT  4.512 29.603 4.536 31.621 ;
     RECT  4.512 31.621 4.632 31.667 ;
     RECT  6 30.469 8.472 31.955 ;
     RECT  83.4 2.151 83.712 32.245 ;
     RECT  7.68 31.955 8.472 32.437 ;
     RECT  9.504 32.341 9.528 32.437 ;
     RECT  45.6 31.379 46.968 32.437 ;
     RECT  51 2.151 51.312 32.437 ;
     RECT  45.6 32.437 47.88 32.579 ;
     RECT  47.424 32.579 47.88 32.723 ;
     RECT  50.592 32.437 51.312 32.771 ;
     RECT  47.424 32.723 47.448 33.539 ;
     RECT  6 31.955 6.024 33.683 ;
     RECT  43.392 32.389 43.416 33.683 ;
     RECT  45.6 32.579 46.056 33.683 ;
     RECT  4.608 31.667 4.632 34.355 ;
     RECT  7.68 32.437 9.528 34.741 ;
     RECT  48.864 31.571 49.464 34.741 ;
     RECT  45.6 33.683 46.008 34.885 ;
     RECT  48.864 34.741 49.608 34.933 ;
     RECT  54.96 34.741 54.984 35.173 ;
     RECT  54.96 35.173 55.128 35.219 ;
     RECT  55.104 35.219 55.128 35.843 ;
     RECT  6.864 34.741 9.528 35.845 ;
     RECT  45.6 34.885 46.2 36.037 ;
     RECT  6.096 35.845 9.528 36.275 ;
     RECT  43.344 35.893 43.368 36.325 ;
     RECT  6.096 36.275 8.112 36.515 ;
     RECT  9.216 36.275 9.528 36.563 ;
     RECT  13.2 2.151 13.512 36.613 ;
     RECT  48.768 34.933 49.608 36.755 ;
     RECT  7.392 36.515 8.112 36.947 ;
     RECT  43.344 36.325 44.328 37.091 ;
     RECT  48.768 36.755 49.128 37.091 ;
     RECT  6.096 36.515 6.12 37.139 ;
     RECT  9.216 36.563 9.24 37.331 ;
     RECT  44.304 37.091 44.328 37.429 ;
     RECT  45.504 36.037 46.2 37.429 ;
     RECT  48.768 37.091 48.888 37.909 ;
     RECT  48.48 37.909 48.888 37.955 ;
     RECT  44.304 37.429 46.2 38.819 ;
     RECT  48.48 37.955 48.504 38.819 ;
     RECT  45.216 38.819 46.2 39.395 ;
     RECT  47.568 39.061 47.592 39.827 ;
     RECT  45.216 39.395 45.912 40.645 ;
     RECT  82.464 32.245 83.712 41.651 ;
     RECT  45.216 40.645 46.104 42.133 ;
     RECT  0.192 29.509 0.216 43.955 ;
     RECT  13.2 36.613 13.656 44.099 ;
     RECT  45.216 42.133 46.728 44.099 ;
     RECT  45.6 44.099 46.728 51.347 ;
     RECT  48.864 39.829 48.888 51.829 ;
     RECT  48.24 51.829 48.888 58.739 ;
     RECT  48.288 58.739 48.312 59.749 ;
     RECT  47.856 59.749 48.312 59.795 ;
     RECT  47.856 59.795 47.88 60.325 ;
     RECT  45.6 51.347 45.912 60.421 ;
     RECT  49.728 59.749 49.752 60.467 ;
     RECT  47.28 60.325 47.88 60.803 ;
     RECT  47.28 60.803 47.304 61.427 ;
     RECT  45.6 60.421 46.2 61.763 ;
     RECT  48.816 62.149 48.84 62.293 ;
     RECT  48.816 62.293 49.704 62.533 ;
     RECT  51 32.771 51.312 62.533 ;
     RECT  48.816 62.533 51.312 62.629 ;
     RECT  2.4 30.611 2.712 62.649 ;
     RECT  7.8 36.947 8.112 62.649 ;
     RECT  13.2 44.099 13.512 62.649 ;
     RECT  18.6 2.151 18.912 62.649 ;
     RECT  24 2.151 24.312 62.649 ;
     RECT  29.4 2.151 29.712 62.649 ;
     RECT  34.8 2.151 35.112 62.649 ;
     RECT  40.2 2.151 40.512 62.649 ;
     RECT  45.6 61.763 45.912 62.649 ;
     RECT  48.72 62.629 51.312 62.649 ;
     RECT  56.4 2.151 56.712 62.649 ;
     RECT  61.8 2.151 62.112 62.649 ;
     RECT  67.2 2.151 67.512 62.649 ;
     RECT  72.6 2.151 72.912 62.649 ;
     RECT  78 2.151 78.312 62.649 ;
     RECT  83.4 41.651 83.712 62.649 ;
     RECT  2.4 62.649 2.52 62.663 ;
     RECT  7.8 62.649 7.92 62.663 ;
     RECT  13.2 62.649 13.32 62.663 ;
     RECT  18.6 62.649 18.72 62.663 ;
     RECT  24 62.649 24.12 62.663 ;
     RECT  29.4 62.649 29.52 62.663 ;
     RECT  34.8 62.649 34.92 62.663 ;
     RECT  40.2 62.649 40.32 62.663 ;
     RECT  45.6 62.649 45.72 62.663 ;
     RECT  48.72 62.649 51.12 62.663 ;
     RECT  56.4 62.649 56.52 62.663 ;
     RECT  61.8 62.649 61.92 62.663 ;
     RECT  67.2 62.649 67.32 62.663 ;
     RECT  72.6 62.649 72.72 62.663 ;
     RECT  78 62.649 78.12 62.663 ;
     RECT  83.4 62.649 83.52 62.663 ;
     RECT  48.72 62.663 50.088 62.725 ;
     RECT  48.528 62.725 50.088 64.784 ;
     RECT  6.312 26.677 7.8 27.157 ;
     RECT  6.312 27.157 7.68 27.781 ;
     RECT  4.536 29.603 5.616 30.323 ;
     RECT  3.528 29.653 4.512 30.611 ;
     RECT  4.536 30.323 6 31.621 ;
     RECT  45.912 30.613 46.944 31.093 ;
     RECT  48.72 31.571 48.864 32.437 ;
     RECT  4.632 31.621 6 33.683 ;
     RECT  8.472 32.341 9.504 32.437 ;
     RECT  47.88 32.437 48.864 32.723 ;
     RECT  49.464 32.437 50.592 32.771 ;
     RECT  46.056 32.579 47.424 33.539 ;
     RECT  47.448 32.723 48.864 33.539 ;
     RECT  46.056 33.539 46.2 33.683 ;
     RECT  48.768 33.539 48.864 34.933 ;
     RECT  46.008 33.683 46.2 34.885 ;
     RECT  49.608 34.741 51 36.755 ;
     RECT  54.984 34.741 56.4 35.173 ;
     RECT  55.128 35.173 56.4 35.843 ;
     RECT  8.112 36.275 9.216 37.331 ;
     RECT  44.328 36.325 45.504 37.429 ;
     RECT  6.12 36.515 7.392 36.947 ;
     RECT  46.2 39.061 47.568 39.395 ;
     RECT  45.912 39.395 47.568 39.827 ;
     RECT  45.912 39.827 46.104 40.645 ;
     RECT  48.24 58.739 48.288 59.749 ;
     RECT  48.312 58.739 48.888 59.749 ;
     RECT  48.312 59.749 49.728 59.795 ;
     RECT  49.752 59.749 51 60.467 ;
     RECT  45.912 60.325 47.28 60.421 ;
     RECT  46.2 60.421 47.28 61.427 ;
     RECT  49.704 62.293 51 62.533 ;
  END
END ot_hgi_sm_pub_cmd_quiet
END LIBRARY
